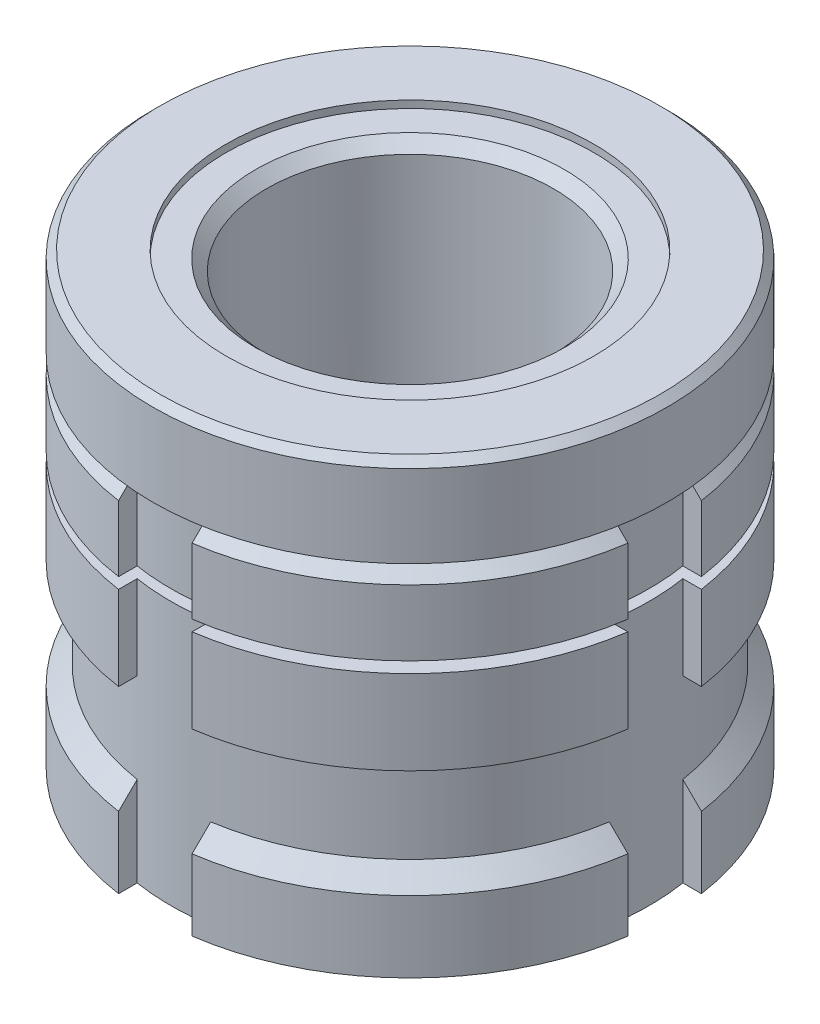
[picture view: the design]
ISO-10303-21;
HEADER;
FILE_DESCRIPTION(('STEP AP214'),'2;1');
FILE_NAME('part.step','',(''),(''),'','','');
FILE_SCHEMA(('AUTOMOTIVE_DESIGN { 1 0 10303 214 1 1 1 1 }'));
ENDSEC;
DATA;
#1=APPLICATION_CONTEXT('core data for automotive mechanical design processes');
#2=APPLICATION_PROTOCOL_DEFINITION('international standard','automotive_design',2000,#1);
#3=PRODUCT_CONTEXT('',#1,'mechanical');
#4=PRODUCT('Part','Part','',(#3));
#5=PRODUCT_RELATED_PRODUCT_CATEGORY('part','',(#4));
#6=PRODUCT_DEFINITION_FORMATION('','',#4);
#7=PRODUCT_DEFINITION_CONTEXT('part definition',#1,'design');
#8=PRODUCT_DEFINITION('design','',#6,#7);
#9=PRODUCT_DEFINITION_SHAPE('','',#8);
#10=(LENGTH_UNIT() NAMED_UNIT(*) SI_UNIT(.MILLI.,.METRE.));
#11=(NAMED_UNIT(*) PLANE_ANGLE_UNIT() SI_UNIT($,.RADIAN.));
#12=(NAMED_UNIT(*) SI_UNIT($,.STERADIAN.) SOLID_ANGLE_UNIT());
#13=UNCERTAINTY_MEASURE_WITH_UNIT(LENGTH_MEASURE(1.E-05),#10,'distance_accuracy_value','');
#14=(GEOMETRIC_REPRESENTATION_CONTEXT(3) GLOBAL_UNCERTAINTY_ASSIGNED_CONTEXT((#13)) GLOBAL_UNIT_ASSIGNED_CONTEXT((#10,
#11,#12)) REPRESENTATION_CONTEXT('',''));
#15=CARTESIAN_POINT('',(0.,0.,0.));
#16=DIRECTION('',(0.,0.,1.));
#17=DIRECTION('',(1.,0.,0.));
#18=AXIS2_PLACEMENT_3D('',#15,#16,#17);
#19=CARTESIAN_POINT('',(0.,24.4,0.));
#20=DIRECTION('',(0.,-1.,0.));
#21=DIRECTION('',(0.,0.,-1.));
#22=AXIS2_PLACEMENT_3D('',#19,#20,#21);
#23=CYLINDRICAL_SURFACE('',#22,35.);
#24=DIRECTION('',(0.,1.,0.));
#25=VECTOR('',#24,1.);
#26=CARTESIAN_POINT('',(-5.00000000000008,-34.8083763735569,34.6410161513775));
#27=LINE('',#26,#25);
#28=CARTESIAN_POINT('',(-5.00000000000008,12.95,34.6410161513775));
#29=VERTEX_POINT('',#28);
#30=CARTESIAN_POINT('',(-5.00000000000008,21.9,34.6410161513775));
#31=VERTEX_POINT('',#30);
#32=EDGE_CURVE('E630',#29,#31,#27,.T.);
#33=ORIENTED_EDGE('',*,*,#32,.T.);
#34=CARTESIAN_POINT('',(0.,21.9,0.));
#35=DIRECTION('',(0.,1.,0.));
#36=DIRECTION('',(0.,0.,1.));
#37=AXIS2_PLACEMENT_3D('',#34,#35,#36);
#38=CIRCLE('',#37,35.);
#39=CARTESIAN_POINT('',(-34.6410161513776,21.9,4.9999999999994));
#40=VERTEX_POINT('',#39);
#41=EDGE_CURVE('E55',#31,#40,#38,.F.);
#42=ORIENTED_EDGE('',*,*,#41,.T.);
#43=DIRECTION('',(0.,1.,0.));
#44=VECTOR('',#43,1.);
#45=CARTESIAN_POINT('',(-34.6410161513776,-34.8083763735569,4.9999999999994));
#46=LINE('',#45,#44);
#47=CARTESIAN_POINT('',(-34.6410161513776,12.95,4.9999999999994));
#48=VERTEX_POINT('',#47);
#49=EDGE_CURVE('E723',#48,#40,#46,.T.);
#50=ORIENTED_EDGE('',*,*,#49,.F.);
#51=CARTESIAN_POINT('',(0.,12.95,0.));
#52=DIRECTION('',(0.,1.,0.));
#53=DIRECTION('',(0.,0.,1.));
#54=AXIS2_PLACEMENT_3D('',#51,#52,#53);
#55=CIRCLE('',#54,35.);
#56=EDGE_CURVE('E632',#48,#29,#55,.T.);
#57=ORIENTED_EDGE('',*,*,#56,.T.);
#58=EDGE_LOOP('',(#33,#42,#50,#57));
#59=FACE_BOUND('',#58,.T.);
#60=ADVANCED_FACE('F39',(#59),#23,.T.);
#61=DIRECTION('',(0.,1.,0.));
#62=VECTOR('',#61,1.);
#63=CARTESIAN_POINT('',(-34.6410161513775,-34.8083763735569,-5.0000000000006));
#64=LINE('',#63,#62);
#65=CARTESIAN_POINT('',(-34.6410161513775,12.95,-5.0000000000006));
#66=VERTEX_POINT('',#65);
#67=CARTESIAN_POINT('',(-34.6410161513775,21.9,-5.0000000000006));
#68=VERTEX_POINT('',#67);
#69=EDGE_CURVE('E714',#66,#68,#64,.T.);
#70=ORIENTED_EDGE('',*,*,#69,.T.);
#71=CARTESIAN_POINT('',(0.,21.9,0.));
#72=DIRECTION('',(0.,1.,0.));
#73=DIRECTION('',(0.,0.,1.));
#74=AXIS2_PLACEMENT_3D('',#71,#72,#73);
#75=CIRCLE('',#74,35.);
#76=CARTESIAN_POINT('',(-5.00000000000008,21.9,-34.6410161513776));
#77=VERTEX_POINT('',#76);
#78=EDGE_CURVE('E409',#68,#77,#75,.F.);
#79=ORIENTED_EDGE('',*,*,#78,.T.);
#80=DIRECTION('',(0.,1.,0.));
#81=VECTOR('',#80,1.);
#82=CARTESIAN_POINT('',(-5.00000000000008,-34.8083763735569,-34.6410161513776));
#83=LINE('',#82,#81);
#84=CARTESIAN_POINT('',(-5.00000000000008,12.95,-34.6410161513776));
#85=VERTEX_POINT('',#84);
#86=EDGE_CURVE('E750',#85,#77,#83,.T.);
#87=ORIENTED_EDGE('',*,*,#86,.F.);
#88=EDGE_CURVE('E1121',#85,#66,#55,.T.);
#89=ORIENTED_EDGE('',*,*,#88,.T.);
#90=EDGE_LOOP('',(#70,#79,#87,#89));
#91=FACE_BOUND('',#90,.T.);
#92=ADVANCED_FACE('F624',(#91),#23,.T.);
#93=DIRECTION('',(0.,1.,0.));
#94=VECTOR('',#93,1.);
#95=CARTESIAN_POINT('',(34.6410161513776,-34.8083763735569,5.00000000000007));
#96=LINE('',#95,#94);
#97=CARTESIAN_POINT('',(34.6410161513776,12.95,5.00000000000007));
#98=VERTEX_POINT('',#97);
#99=CARTESIAN_POINT('',(34.6410161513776,21.9,5.00000000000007));
#100=VERTEX_POINT('',#99);
#101=EDGE_CURVE('E769',#98,#100,#96,.T.);
#102=ORIENTED_EDGE('',*,*,#101,.T.);
#103=CARTESIAN_POINT('',(0.,21.9,0.));
#104=DIRECTION('',(0.,1.,0.));
#105=DIRECTION('',(0.,0.,1.));
#106=AXIS2_PLACEMENT_3D('',#103,#104,#105);
#107=CIRCLE('',#106,35.);
#108=CARTESIAN_POINT('',(5.00000000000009,21.9,34.6410161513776));
#109=VERTEX_POINT('',#108);
#110=EDGE_CURVE('E1137',#100,#109,#107,.F.);
#111=ORIENTED_EDGE('',*,*,#110,.T.);
#112=DIRECTION('',(0.,1.,0.));
#113=VECTOR('',#112,1.);
#114=CARTESIAN_POINT('',(5.00000000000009,-34.8083763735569,34.6410161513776));
#115=LINE('',#114,#113);
#116=CARTESIAN_POINT('',(5.00000000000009,12.95,34.6410161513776));
#117=VERTEX_POINT('',#116);
#118=EDGE_CURVE('E824',#117,#109,#115,.T.);
#119=ORIENTED_EDGE('',*,*,#118,.F.);
#120=EDGE_CURVE('E976',#117,#98,#55,.T.);
#121=ORIENTED_EDGE('',*,*,#120,.T.);
#122=EDGE_LOOP('',(#102,#111,#119,#121));
#123=FACE_BOUND('',#122,.T.);
#124=ADVANCED_FACE('F603',(#123),#23,.T.);
#125=CARTESIAN_POINT('',(0.,12.95,35.));
#126=DIRECTION('',(0.,1.,0.));
#127=DIRECTION('',(0.,0.,1.));
#128=AXIS2_PLACEMENT_3D('',#125,#126,#127);
#129=PLANE('',#128);
#130=CARTESIAN_POINT('',(0.,12.95,0.));
#131=DIRECTION('',(0.,1.,0.));
#132=DIRECTION('',(0.,0.,1.));
#133=AXIS2_PLACEMENT_3D('',#130,#131,#132);
#134=CIRCLE('',#133,25.);
#135=CARTESIAN_POINT('',(0.,12.95,25.));
#136=VERTEX_POINT('',#135);
#137=EDGE_CURVE('E979',#136,#136,#134,.T.);
#138=ORIENTED_EDGE('',*,*,#137,.T.);
#139=EDGE_LOOP('',(#138));
#140=FACE_BOUND('',#139,.T.);
#141=ORIENTED_EDGE('',*,*,#56,.F.);
#142=DIRECTION('',(1.,0.,0.));
#143=VECTOR('',#142,1.);
#144=CARTESIAN_POINT('',(0.,12.95,4.9999999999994));
#145=LINE('',#144,#143);
#146=CARTESIAN_POINT('',(-32.1130814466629,12.95,4.9999999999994));
#147=VERTEX_POINT('',#146);
#148=EDGE_CURVE('E949',#48,#147,#145,.T.);
#149=ORIENTED_EDGE('',*,*,#148,.T.);
#150=CARTESIAN_POINT('',(0.,12.95,0.));
#151=DIRECTION('',(0.,1.,0.));
#152=DIRECTION('',(0.,0.,1.));
#153=AXIS2_PLACEMENT_3D('',#150,#151,#152);
#154=CIRCLE('',#153,32.5);
#155=CARTESIAN_POINT('',(-32.1130814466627,12.95,-5.0000000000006));
#156=VERTEX_POINT('',#155);
#157=EDGE_CURVE('E938',#147,#156,#154,.F.);
#158=ORIENTED_EDGE('',*,*,#157,.T.);
#159=DIRECTION('',(-1.,0.,0.));
#160=VECTOR('',#159,1.);
#161=CARTESIAN_POINT('',(0.,12.95,-5.0000000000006));
#162=LINE('',#161,#160);
#163=EDGE_CURVE('E930',#156,#66,#162,.T.);
#164=ORIENTED_EDGE('',*,*,#163,.T.);
#165=ORIENTED_EDGE('',*,*,#88,.F.);
#166=DIRECTION('',(0.,0.,1.));
#167=VECTOR('',#166,1.);
#168=CARTESIAN_POINT('',(-5.00000000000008,12.95,35.));
#169=LINE('',#168,#167);
#170=CARTESIAN_POINT('',(-5.00000000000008,12.95,-32.1130814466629));
#171=VERTEX_POINT('',#170);
#172=EDGE_CURVE('E918',#85,#171,#169,.T.);
#173=ORIENTED_EDGE('',*,*,#172,.T.);
#174=CARTESIAN_POINT('',(0.,12.95,0.));
#175=DIRECTION('',(0.,1.,0.));
#176=DIRECTION('',(0.,0.,1.));
#177=AXIS2_PLACEMENT_3D('',#174,#175,#176);
#178=CIRCLE('',#177,32.5000000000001);
#179=CARTESIAN_POINT('',(5.00000000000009,12.95,-32.1130814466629));
#180=VERTEX_POINT('',#179);
#181=EDGE_CURVE('E907',#171,#180,#178,.F.);
#182=ORIENTED_EDGE('',*,*,#181,.T.);
#183=DIRECTION('',(0.,0.,-1.));
#184=VECTOR('',#183,1.);
#185=CARTESIAN_POINT('',(5.00000000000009,12.95,35.));
#186=LINE('',#185,#184);
#187=CARTESIAN_POINT('',(5.00000000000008,12.95,-34.6410161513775));
#188=VERTEX_POINT('',#187);
#189=EDGE_CURVE('E368',#180,#188,#186,.T.);
#190=ORIENTED_EDGE('',*,*,#189,.T.);
#191=CARTESIAN_POINT('',(34.6410161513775,12.95,-5.0000000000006));
#192=VERTEX_POINT('',#191);
#193=EDGE_CURVE('E980',#192,#188,#55,.T.);
#194=ORIENTED_EDGE('',*,*,#193,.F.);
#195=DIRECTION('',(-1.,0.,0.));
#196=VECTOR('',#195,1.);
#197=CARTESIAN_POINT('',(0.,12.95,-5.0000000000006));
#198=LINE('',#197,#196);
#199=CARTESIAN_POINT('',(32.1130814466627,12.95,-5.0000000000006));
#200=VERTEX_POINT('',#199);
#201=EDGE_CURVE('E877',#192,#200,#198,.T.);
#202=ORIENTED_EDGE('',*,*,#201,.T.);
#203=CARTESIAN_POINT('',(0.,12.95,0.));
#204=DIRECTION('',(0.,1.,0.));
#205=DIRECTION('',(0.,0.,1.));
#206=AXIS2_PLACEMENT_3D('',#203,#204,#205);
#207=CIRCLE('',#206,32.5);
#208=CARTESIAN_POINT('',(32.1130814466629,12.95,5.00000000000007));
#209=VERTEX_POINT('',#208);
#210=EDGE_CURVE('E865',#200,#209,#207,.F.);
#211=ORIENTED_EDGE('',*,*,#210,.T.);
#212=DIRECTION('',(1.,0.,0.));
#213=VECTOR('',#212,1.);
#214=CARTESIAN_POINT('',(0.,12.95,5.00000000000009));
#215=LINE('',#214,#213);
#216=EDGE_CURVE('E889',#209,#98,#215,.T.);
#217=ORIENTED_EDGE('',*,*,#216,.T.);
#218=ORIENTED_EDGE('',*,*,#120,.F.);
#219=DIRECTION('',(0.,0.,-1.));
#220=VECTOR('',#219,1.);
#221=CARTESIAN_POINT('',(5.00000000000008,12.95,35.));
#222=LINE('',#221,#220);
#223=CARTESIAN_POINT('',(5.00000000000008,12.95,32.1130814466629));
#224=VERTEX_POINT('',#223);
#225=EDGE_CURVE('E846',#117,#224,#222,.T.);
#226=ORIENTED_EDGE('',*,*,#225,.T.);
#227=CARTESIAN_POINT('',(0.,12.95,0.));
#228=DIRECTION('',(0.,1.,0.));
#229=DIRECTION('',(0.,0.,1.));
#230=AXIS2_PLACEMENT_3D('',#227,#228,#229);
#231=CIRCLE('',#230,32.5);
#232=CARTESIAN_POINT('',(-5.00000000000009,12.95,32.1130814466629));
#233=VERTEX_POINT('',#232);
#234=EDGE_CURVE('E834',#224,#233,#231,.F.);
#235=ORIENTED_EDGE('',*,*,#234,.T.);
#236=DIRECTION('',(0.,0.,1.));
#237=VECTOR('',#236,1.);
#238=CARTESIAN_POINT('',(-5.00000000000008,12.95,35.));
#239=LINE('',#238,#237);
#240=EDGE_CURVE('E858',#233,#29,#239,.T.);
#241=ORIENTED_EDGE('',*,*,#240,.T.);
#242=EDGE_LOOP('',(#141,#149,#158,#164,#165,#173,#182,#190,#194,#202,#211,#217,#218,#226,#235,#241));
#243=FACE_BOUND('',#242,.T.);
#244=ADVANCED_FACE('F599',(#140,#243),#129,.F.);
#245=CARTESIAN_POINT('',(0.,11.45,35.));
#246=DIRECTION('',(0.,-1.,0.));
#247=DIRECTION('',(0.,0.,-1.));
#248=AXIS2_PLACEMENT_3D('',#245,#246,#247);
#249=PLANE('',#248);
#250=CARTESIAN_POINT('',(0.,11.45,0.));
#251=DIRECTION('',(0.,1.,0.));
#252=DIRECTION('',(0.,0.,1.));
#253=AXIS2_PLACEMENT_3D('',#250,#251,#252);
#254=CIRCLE('',#253,25.);
#255=CARTESIAN_POINT('',(0.,11.45,25.));
#256=VERTEX_POINT('',#255);
#257=EDGE_CURVE('E958',#256,#256,#254,.T.);
#258=ORIENTED_EDGE('',*,*,#257,.F.);
#259=EDGE_LOOP('',(#258));
#260=FACE_BOUND('',#259,.T.);
#261=CARTESIAN_POINT('',(0.,11.45,0.));
#262=DIRECTION('',(0.,-1.,0.));
#263=DIRECTION('',(0.,0.,-1.));
#264=AXIS2_PLACEMENT_3D('',#261,#262,#263);
#265=CIRCLE('',#264,32.5);
#266=CARTESIAN_POINT('',(-32.1130814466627,11.45,-5.0000000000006));
#267=VERTEX_POINT('',#266);
#268=CARTESIAN_POINT('',(-32.1130814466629,11.45,4.9999999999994));
#269=VERTEX_POINT('',#268);
#270=EDGE_CURVE('E934',#267,#269,#265,.F.);
#271=ORIENTED_EDGE('',*,*,#270,.T.);
#272=DIRECTION('',(-1.,0.,0.));
#273=VECTOR('',#272,1.);
#274=CARTESIAN_POINT('',(0.,11.45,4.9999999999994));
#275=LINE('',#274,#273);
#276=CARTESIAN_POINT('',(-34.6410161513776,11.45,4.9999999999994));
#277=VERTEX_POINT('',#276);
#278=EDGE_CURVE('E945',#269,#277,#275,.T.);
#279=ORIENTED_EDGE('',*,*,#278,.T.);
#280=CARTESIAN_POINT('',(0.,11.45,0.));
#281=DIRECTION('',(0.,1.,0.));
#282=DIRECTION('',(0.,0.,1.));
#283=AXIS2_PLACEMENT_3D('',#280,#281,#282);
#284=CIRCLE('',#283,35.);
#285=CARTESIAN_POINT('',(-5.00000000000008,11.45,34.6410161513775));
#286=VERTEX_POINT('',#285);
#287=EDGE_CURVE('E970',#277,#286,#284,.T.);
#288=ORIENTED_EDGE('',*,*,#287,.T.);
#289=DIRECTION('',(0.,0.,-1.));
#290=VECTOR('',#289,1.);
#291=CARTESIAN_POINT('',(-5.00000000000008,11.45,35.));
#292=LINE('',#291,#290);
#293=CARTESIAN_POINT('',(-5.00000000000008,11.45,32.1130814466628));
#294=VERTEX_POINT('',#293);
#295=EDGE_CURVE('E854',#286,#294,#292,.T.);
#296=ORIENTED_EDGE('',*,*,#295,.T.);
#297=CARTESIAN_POINT('',(0.,11.45,0.));
#298=DIRECTION('',(0.,-1.,0.));
#299=DIRECTION('',(0.,0.,-1.));
#300=AXIS2_PLACEMENT_3D('',#297,#298,#299);
#301=CIRCLE('',#300,32.5);
#302=CARTESIAN_POINT('',(5.00000000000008,11.45,32.1130814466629));
#303=VERTEX_POINT('',#302);
#304=EDGE_CURVE('E732',#294,#303,#301,.F.);
#305=ORIENTED_EDGE('',*,*,#304,.T.);
#306=DIRECTION('',(0.,0.,1.));
#307=VECTOR('',#306,1.);
#308=CARTESIAN_POINT('',(5.00000000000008,11.45,35.));
#309=LINE('',#308,#307);
#310=CARTESIAN_POINT('',(5.00000000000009,11.45,34.6410161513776));
#311=VERTEX_POINT('',#310);
#312=EDGE_CURVE('E842',#303,#311,#309,.T.);
#313=ORIENTED_EDGE('',*,*,#312,.T.);
#314=CARTESIAN_POINT('',(34.6410161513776,11.45,5.00000000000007));
#315=VERTEX_POINT('',#314);
#316=EDGE_CURVE('E971',#311,#315,#284,.T.);
#317=ORIENTED_EDGE('',*,*,#316,.T.);
#318=DIRECTION('',(-1.,0.,0.));
#319=VECTOR('',#318,1.);
#320=CARTESIAN_POINT('',(0.,11.45,5.00000000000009));
#321=LINE('',#320,#319);
#322=CARTESIAN_POINT('',(32.1130814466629,11.45,5.00000000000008));
#323=VERTEX_POINT('',#322);
#324=EDGE_CURVE('E885',#315,#323,#321,.T.);
#325=ORIENTED_EDGE('',*,*,#324,.T.);
#326=CARTESIAN_POINT('',(0.,11.45,0.));
#327=DIRECTION('',(0.,-1.,0.));
#328=DIRECTION('',(0.,0.,-1.));
#329=AXIS2_PLACEMENT_3D('',#326,#327,#328);
#330=CIRCLE('',#329,32.5);
#331=CARTESIAN_POINT('',(32.1130814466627,11.45,-5.0000000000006));
#332=VERTEX_POINT('',#331);
#333=EDGE_CURVE('E861',#323,#332,#330,.F.);
#334=ORIENTED_EDGE('',*,*,#333,.T.);
#335=DIRECTION('',(1.,0.,0.));
#336=VECTOR('',#335,1.);
#337=CARTESIAN_POINT('',(0.,11.45,-5.0000000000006));
#338=LINE('',#337,#336);
#339=CARTESIAN_POINT('',(34.6410161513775,11.45,-5.0000000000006));
#340=VERTEX_POINT('',#339);
#341=EDGE_CURVE('E873',#332,#340,#338,.T.);
#342=ORIENTED_EDGE('',*,*,#341,.T.);
#343=CARTESIAN_POINT('',(5.00000000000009,11.45,-34.6410161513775));
#344=VERTEX_POINT('',#343);
#345=EDGE_CURVE('E975',#340,#344,#284,.T.);
#346=ORIENTED_EDGE('',*,*,#345,.T.);
#347=DIRECTION('',(0.,0.,1.));
#348=VECTOR('',#347,1.);
#349=CARTESIAN_POINT('',(5.00000000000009,11.45,35.));
#350=LINE('',#349,#348);
#351=CARTESIAN_POINT('',(5.00000000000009,11.45,-32.1130814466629));
#352=VERTEX_POINT('',#351);
#353=EDGE_CURVE('E897',#344,#352,#350,.T.);
#354=ORIENTED_EDGE('',*,*,#353,.T.);
#355=CARTESIAN_POINT('',(0.,11.45,0.));
#356=DIRECTION('',(0.,-1.,0.));
#357=DIRECTION('',(0.,0.,-1.));
#358=AXIS2_PLACEMENT_3D('',#355,#356,#357);
#359=CIRCLE('',#358,32.5000000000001);
#360=CARTESIAN_POINT('',(-5.00000000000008,11.45,-32.1130814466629));
#361=VERTEX_POINT('',#360);
#362=EDGE_CURVE('E903',#352,#361,#359,.F.);
#363=ORIENTED_EDGE('',*,*,#362,.T.);
#364=DIRECTION('',(0.,0.,-1.));
#365=VECTOR('',#364,1.);
#366=CARTESIAN_POINT('',(-5.00000000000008,11.45,35.));
#367=LINE('',#366,#365);
#368=CARTESIAN_POINT('',(-5.00000000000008,11.45,-34.6410161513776));
#369=VERTEX_POINT('',#368);
#370=EDGE_CURVE('E914',#361,#369,#367,.T.);
#371=ORIENTED_EDGE('',*,*,#370,.T.);
#372=CARTESIAN_POINT('',(-34.6410161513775,11.45,-5.0000000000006));
#373=VERTEX_POINT('',#372);
#374=EDGE_CURVE('E1180',#369,#373,#284,.T.);
#375=ORIENTED_EDGE('',*,*,#374,.T.);
#376=DIRECTION('',(1.,0.,0.));
#377=VECTOR('',#376,1.);
#378=CARTESIAN_POINT('',(0.,11.45,-5.0000000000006));
#379=LINE('',#378,#377);
#380=EDGE_CURVE('E926',#373,#267,#379,.T.);
#381=ORIENTED_EDGE('',*,*,#380,.T.);
#382=EDGE_LOOP('',(#271,#279,#288,#296,#305,#313,#317,#325,#334,#342,#346,#354,#363,#371,#375,#381));
#383=FACE_BOUND('',#382,.T.);
#384=ADVANCED_FACE('F595',(#260,#383),#249,.F.);
#385=CARTESIAN_POINT('',(0.,0.,0.));
#386=DIRECTION('',(0.,1.,0.));
#387=DIRECTION('',(0.,0.,1.));
#388=AXIS2_PLACEMENT_3D('',#385,#386,#387);
#389=PLANE('',#388);
#390=CARTESIAN_POINT('',(0.,0.,0.));
#391=DIRECTION('',(0.,1.,0.));
#392=DIRECTION('',(0.,0.,1.));
#393=AXIS2_PLACEMENT_3D('',#390,#391,#392);
#394=CIRCLE('',#393,35.);
#395=CARTESIAN_POINT('',(-34.6410161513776,0.,4.9999999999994));
#396=VERTEX_POINT('',#395);
#397=CARTESIAN_POINT('',(-5.00000000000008,0.,34.6410161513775));
#398=VERTEX_POINT('',#397);
#399=EDGE_CURVE('E984',#396,#398,#394,.T.);
#400=ORIENTED_EDGE('',*,*,#399,.F.);
#401=DIRECTION('',(1.,0.,0.));
#402=VECTOR('',#401,1.);
#403=CARTESIAN_POINT('',(0.,0.,4.9999999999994));
#404=LINE('',#403,#402);
#405=CARTESIAN_POINT('',(-32.1130814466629,0.,4.9999999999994));
#406=VERTEX_POINT('',#405);
#407=EDGE_CURVE('E941',#396,#406,#404,.T.);
#408=ORIENTED_EDGE('',*,*,#407,.T.);
#409=CARTESIAN_POINT('',(0.,0.,0.));
#410=DIRECTION('',(0.,-1.,0.));
#411=DIRECTION('',(0.,0.,-1.));
#412=AXIS2_PLACEMENT_3D('',#409,#410,#411);
#413=CIRCLE('',#412,32.5);
#414=CARTESIAN_POINT('',(-5.00000000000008,0.,32.1130814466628));
#415=VERTEX_POINT('',#414);
#416=EDGE_CURVE('E1077',#415,#406,#413,.T.);
#417=ORIENTED_EDGE('',*,*,#416,.F.);
#418=DIRECTION('',(0.,0.,1.));
#419=VECTOR('',#418,1.);
#420=CARTESIAN_POINT('',(-5.00000000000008,0.,0.));
#421=LINE('',#420,#419);
#422=EDGE_CURVE('E850',#415,#398,#421,.T.);
#423=ORIENTED_EDGE('',*,*,#422,.T.);
#424=EDGE_LOOP('',(#400,#408,#417,#423));
#425=FACE_BOUND('',#424,.T.);
#426=ADVANCED_FACE('F598',(#425),#389,.F.);
#427=CARTESIAN_POINT('',(-32.1130814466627,0.,-5.0000000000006));
#428=VERTEX_POINT('',#427);
#429=CARTESIAN_POINT('',(-5.00000000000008,0.,-32.1130814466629));
#430=VERTEX_POINT('',#429);
#431=EDGE_CURVE('E966',#428,#430,#413,.T.);
#432=ORIENTED_EDGE('',*,*,#431,.F.);
#433=DIRECTION('',(-1.,0.,0.));
#434=VECTOR('',#433,1.);
#435=CARTESIAN_POINT('',(0.,0.,-5.0000000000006));
#436=LINE('',#435,#434);
#437=CARTESIAN_POINT('',(-34.6410161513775,0.,-5.0000000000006));
#438=VERTEX_POINT('',#437);
#439=EDGE_CURVE('E922',#428,#438,#436,.T.);
#440=ORIENTED_EDGE('',*,*,#439,.T.);
#441=CARTESIAN_POINT('',(-5.00000000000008,0.,-34.6410161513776));
#442=VERTEX_POINT('',#441);
#443=EDGE_CURVE('E1080',#442,#438,#394,.T.);
#444=ORIENTED_EDGE('',*,*,#443,.F.);
#445=DIRECTION('',(0.,0.,1.));
#446=VECTOR('',#445,1.);
#447=CARTESIAN_POINT('',(-5.00000000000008,0.,0.));
#448=LINE('',#447,#446);
#449=EDGE_CURVE('E910',#442,#430,#448,.T.);
#450=ORIENTED_EDGE('',*,*,#449,.T.);
#451=EDGE_LOOP('',(#432,#440,#444,#450));
#452=FACE_BOUND('',#451,.T.);
#453=ADVANCED_FACE('F618',(#452),#389,.F.);
#454=CARTESIAN_POINT('',(32.1130814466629,0.,5.00000000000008));
#455=VERTEX_POINT('',#454);
#456=CARTESIAN_POINT('',(5.00000000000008,0.,32.1130814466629));
#457=VERTEX_POINT('',#456);
#458=EDGE_CURVE('E965',#455,#457,#413,.T.);
#459=ORIENTED_EDGE('',*,*,#458,.F.);
#460=DIRECTION('',(1.,0.,0.));
#461=VECTOR('',#460,1.);
#462=CARTESIAN_POINT('',(0.,0.,5.00000000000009));
#463=LINE('',#462,#461);
#464=CARTESIAN_POINT('',(34.6410161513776,0.,5.00000000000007));
#465=VERTEX_POINT('',#464);
#466=EDGE_CURVE('E881',#455,#465,#463,.T.);
#467=ORIENTED_EDGE('',*,*,#466,.T.);
#468=CARTESIAN_POINT('',(5.00000000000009,0.,34.6410161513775));
#469=VERTEX_POINT('',#468);
#470=EDGE_CURVE('E985',#469,#465,#394,.T.);
#471=ORIENTED_EDGE('',*,*,#470,.F.);
#472=DIRECTION('',(0.,0.,-1.));
#473=VECTOR('',#472,1.);
#474=CARTESIAN_POINT('',(5.00000000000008,0.,0.));
#475=LINE('',#474,#473);
#476=EDGE_CURVE('E838',#469,#457,#475,.T.);
#477=ORIENTED_EDGE('',*,*,#476,.T.);
#478=EDGE_LOOP('',(#459,#467,#471,#477));
#479=FACE_BOUND('',#478,.T.);
#480=ADVANCED_FACE('F611',(#479),#389,.F.);
#481=ORIENTED_EDGE('',*,*,#287,.F.);
#482=EDGE_CURVE('E733',#396,#277,#46,.T.);
#483=ORIENTED_EDGE('',*,*,#482,.F.);
#484=ORIENTED_EDGE('',*,*,#399,.T.);
#485=EDGE_CURVE('E636',#398,#286,#27,.T.);
#486=ORIENTED_EDGE('',*,*,#485,.T.);
#487=EDGE_LOOP('',(#481,#483,#484,#486));
#488=FACE_BOUND('',#487,.T.);
#489=ADVANCED_FACE('F621',(#488),#23,.T.);
#490=ORIENTED_EDGE('',*,*,#443,.T.);
#491=EDGE_CURVE('E724',#438,#373,#64,.T.);
#492=ORIENTED_EDGE('',*,*,#491,.T.);
#493=ORIENTED_EDGE('',*,*,#374,.F.);
#494=EDGE_CURVE('E761',#442,#369,#83,.T.);
#495=ORIENTED_EDGE('',*,*,#494,.F.);
#496=EDGE_LOOP('',(#490,#492,#493,#495));
#497=FACE_BOUND('',#496,.T.);
#498=ADVANCED_FACE('F1181',(#497),#23,.T.);
#499=ORIENTED_EDGE('',*,*,#470,.T.);
#500=EDGE_CURVE('E795',#465,#315,#96,.T.);
#501=ORIENTED_EDGE('',*,*,#500,.T.);
#502=ORIENTED_EDGE('',*,*,#316,.F.);
#503=EDGE_CURVE('E823',#469,#311,#115,.T.);
#504=ORIENTED_EDGE('',*,*,#503,.F.);
#505=EDGE_LOOP('',(#499,#501,#502,#504));
#506=FACE_BOUND('',#505,.T.);
#507=ADVANCED_FACE('F1204',(#506),#23,.T.);
#508=CARTESIAN_POINT('',(0.,-12.2,0.));
#509=DIRECTION('',(0.,-1.,0.));
#510=DIRECTION('',(0.,0.,-1.));
#511=AXIS2_PLACEMENT_3D('',#508,#509,#510);
#512=CYLINDRICAL_SURFACE('',#511,35.);
#513=CARTESIAN_POINT('',(-5.00000000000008,-24.4,34.6410161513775));
#514=VERTEX_POINT('',#513);
#515=CARTESIAN_POINT('',(-5.00000000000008,-14.7,34.6410161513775));
#516=VERTEX_POINT('',#515);
#517=EDGE_CURVE('E639',#514,#516,#27,.T.);
#518=ORIENTED_EDGE('',*,*,#517,.T.);
#519=CARTESIAN_POINT('',(0.,-14.7,0.));
#520=DIRECTION('',(0.,-1.,0.));
#521=DIRECTION('',(0.,0.,-1.));
#522=AXIS2_PLACEMENT_3D('',#519,#520,#521);
#523=CIRCLE('',#522,35.);
#524=CARTESIAN_POINT('',(-34.6410161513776,-14.7,4.9999999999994));
#525=VERTEX_POINT('',#524);
#526=EDGE_CURVE('E532',#516,#525,#523,.T.);
#527=ORIENTED_EDGE('',*,*,#526,.T.);
#528=CARTESIAN_POINT('',(-34.6410161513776,-24.4,4.9999999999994));
#529=VERTEX_POINT('',#528);
#530=EDGE_CURVE('E730',#529,#525,#46,.T.);
#531=ORIENTED_EDGE('',*,*,#530,.F.);
#532=CARTESIAN_POINT('',(0.,-24.4,0.));
#533=DIRECTION('',(0.,-1.,0.));
#534=DIRECTION('',(0.,0.,-1.));
#535=AXIS2_PLACEMENT_3D('',#532,#533,#534);
#536=CIRCLE('',#535,35.);
#537=EDGE_CURVE('E689',#514,#529,#536,.T.);
#538=ORIENTED_EDGE('',*,*,#537,.F.);
#539=EDGE_LOOP('',(#518,#527,#531,#538));
#540=FACE_BOUND('',#539,.T.);
#541=ADVANCED_FACE('F584',(#540),#512,.T.);
#542=CARTESIAN_POINT('',(-34.6410161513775,-24.4,-5.0000000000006));
#543=VERTEX_POINT('',#542);
#544=CARTESIAN_POINT('',(-34.6410161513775,-14.7,-5.0000000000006));
#545=VERTEX_POINT('',#544);
#546=EDGE_CURVE('E719',#543,#545,#64,.T.);
#547=ORIENTED_EDGE('',*,*,#546,.T.);
#548=CARTESIAN_POINT('',(0.,-14.7,0.));
#549=DIRECTION('',(0.,-1.,0.));
#550=DIRECTION('',(0.,0.,-1.));
#551=AXIS2_PLACEMENT_3D('',#548,#549,#550);
#552=CIRCLE('',#551,35.);
#553=CARTESIAN_POINT('',(-5.00000000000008,-14.7,-34.6410161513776));
#554=VERTEX_POINT('',#553);
#555=EDGE_CURVE('E992',#545,#554,#552,.T.);
#556=ORIENTED_EDGE('',*,*,#555,.T.);
#557=CARTESIAN_POINT('',(-5.00000000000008,-24.4,-34.6410161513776));
#558=VERTEX_POINT('',#557);
#559=EDGE_CURVE('E707',#558,#554,#83,.T.);
#560=ORIENTED_EDGE('',*,*,#559,.F.);
#561=EDGE_CURVE('E953',#543,#558,#536,.T.);
#562=ORIENTED_EDGE('',*,*,#561,.F.);
#563=EDGE_LOOP('',(#547,#556,#560,#562));
#564=FACE_BOUND('',#563,.T.);
#565=ADVANCED_FACE('F1040',(#564),#512,.T.);
#566=CARTESIAN_POINT('',(34.6410161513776,-24.4,5.00000000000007));
#567=VERTEX_POINT('',#566);
#568=CARTESIAN_POINT('',(34.6410161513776,-14.7,5.00000000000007));
#569=VERTEX_POINT('',#568);
#570=EDGE_CURVE('E791',#567,#569,#96,.T.);
#571=ORIENTED_EDGE('',*,*,#570,.T.);
#572=CARTESIAN_POINT('',(0.,-14.7,0.));
#573=DIRECTION('',(0.,-1.,0.));
#574=DIRECTION('',(0.,0.,-1.));
#575=AXIS2_PLACEMENT_3D('',#572,#573,#574);
#576=CIRCLE('',#575,35.);
#577=CARTESIAN_POINT('',(5.00000000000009,-14.7,34.6410161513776));
#578=VERTEX_POINT('',#577);
#579=EDGE_CURVE('E1148',#569,#578,#576,.T.);
#580=ORIENTED_EDGE('',*,*,#579,.T.);
#581=CARTESIAN_POINT('',(5.00000000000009,-24.4,34.6410161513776));
#582=VERTEX_POINT('',#581);
#583=EDGE_CURVE('E816',#582,#578,#115,.T.);
#584=ORIENTED_EDGE('',*,*,#583,.F.);
#585=EDGE_CURVE('E959',#567,#582,#536,.T.);
#586=ORIENTED_EDGE('',*,*,#585,.F.);
#587=EDGE_LOOP('',(#571,#580,#584,#586));
#588=FACE_BOUND('',#587,.T.);
#589=ADVANCED_FACE('F585',(#588),#512,.T.);
#590=CARTESIAN_POINT('',(0.,-24.4,0.));
#591=DIRECTION('',(0.,-1.,0.));
#592=DIRECTION('',(0.,0.,-1.));
#593=AXIS2_PLACEMENT_3D('',#590,#591,#592);
#594=PLANE('',#593);
#595=CARTESIAN_POINT('',(0.,-24.4,0.));
#596=DIRECTION('',(0.,-1.,0.));
#597=DIRECTION('',(0.,0.,-1.));
#598=AXIS2_PLACEMENT_3D('',#595,#596,#597);
#599=CIRCLE('',#598,21.);
#600=CARTESIAN_POINT('',(0.,-24.4,-21.));
#601=VERTEX_POINT('',#600);
#602=EDGE_CURVE('E661',#601,#601,#599,.F.);
#603=ORIENTED_EDGE('',*,*,#602,.T.);
#604=EDGE_LOOP('',(#603));
#605=FACE_BOUND('',#604,.T.);
#606=DIRECTION('',(1.,0.,0.));
#607=VECTOR('',#606,1.);
#608=CARTESIAN_POINT('',(-32.1130814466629,-24.4,4.9999999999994));
#609=LINE('',#608,#607);
#610=CARTESIAN_POINT('',(-32.1130814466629,-24.4,4.9999999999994));
#611=VERTEX_POINT('',#610);
#612=EDGE_CURVE('E684',#529,#611,#609,.T.);
#613=ORIENTED_EDGE('',*,*,#612,.T.);
#614=CARTESIAN_POINT('',(0.,-24.4,0.));
#615=DIRECTION('',(0.,-1.,0.));
#616=DIRECTION('',(0.,0.,-1.));
#617=AXIS2_PLACEMENT_3D('',#614,#615,#616);
#618=CIRCLE('',#617,32.5);
#619=CARTESIAN_POINT('',(-32.1130814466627,-24.4,-5.0000000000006));
#620=VERTEX_POINT('',#619);
#621=EDGE_CURVE('E686',#611,#620,#618,.T.);
#622=ORIENTED_EDGE('',*,*,#621,.T.);
#623=DIRECTION('',(-1.,0.,0.));
#624=VECTOR('',#623,1.);
#625=CARTESIAN_POINT('',(-34.6410161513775,-24.4,-5.0000000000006));
#626=LINE('',#625,#624);
#627=EDGE_CURVE('E711',#620,#543,#626,.T.);
#628=ORIENTED_EDGE('',*,*,#627,.T.);
#629=ORIENTED_EDGE('',*,*,#561,.T.);
#630=DIRECTION('',(0.,0.,1.));
#631=VECTOR('',#630,1.);
#632=CARTESIAN_POINT('',(-5.00000000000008,-24.4,-34.6410161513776));
#633=LINE('',#632,#631);
#634=CARTESIAN_POINT('',(-5.00000000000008,-24.4,-32.1130814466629));
#635=VERTEX_POINT('',#634);
#636=EDGE_CURVE('E359',#558,#635,#633,.T.);
#637=ORIENTED_EDGE('',*,*,#636,.T.);
#638=CARTESIAN_POINT('',(0.,-24.4,0.));
#639=DIRECTION('',(0.,-1.,0.));
#640=DIRECTION('',(0.,0.,-1.));
#641=AXIS2_PLACEMENT_3D('',#638,#639,#640);
#642=CIRCLE('',#641,32.5000000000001);
#643=CARTESIAN_POINT('',(5.00000000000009,-24.4,-32.1130814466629));
#644=VERTEX_POINT('',#643);
#645=EDGE_CURVE('E371',#635,#644,#642,.T.);
#646=ORIENTED_EDGE('',*,*,#645,.T.);
#647=DIRECTION('',(0.,0.,-1.));
#648=VECTOR('',#647,1.);
#649=CARTESIAN_POINT('',(5.00000000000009,-24.4,-32.1130814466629));
#650=LINE('',#649,#648);
#651=CARTESIAN_POINT('',(5.00000000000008,-24.4,-34.6410161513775));
#652=VERTEX_POINT('',#651);
#653=EDGE_CURVE('E738',#644,#652,#650,.T.);
#654=ORIENTED_EDGE('',*,*,#653,.T.);
#655=CARTESIAN_POINT('',(34.6410161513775,-24.4,-5.00000000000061));
#656=VERTEX_POINT('',#655);
#657=EDGE_CURVE('E954',#652,#656,#536,.T.);
#658=ORIENTED_EDGE('',*,*,#657,.T.);
#659=DIRECTION('',(-1.,0.,0.));
#660=VECTOR('',#659,1.);
#661=CARTESIAN_POINT('',(32.1130814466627,-24.4,-5.0000000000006));
#662=LINE('',#661,#660);
#663=CARTESIAN_POINT('',(32.1130814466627,-24.4,-5.0000000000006));
#664=VERTEX_POINT('',#663);
#665=EDGE_CURVE('E776',#656,#664,#662,.T.);
#666=ORIENTED_EDGE('',*,*,#665,.T.);
#667=CARTESIAN_POINT('',(0.,-24.4,0.));
#668=DIRECTION('',(0.,-1.,0.));
#669=DIRECTION('',(0.,0.,-1.));
#670=AXIS2_PLACEMENT_3D('',#667,#668,#669);
#671=CIRCLE('',#670,32.5);
#672=CARTESIAN_POINT('',(32.1130814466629,-24.4,5.00000000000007));
#673=VERTEX_POINT('',#672);
#674=EDGE_CURVE('E770',#664,#673,#671,.T.);
#675=ORIENTED_EDGE('',*,*,#674,.T.);
#676=DIRECTION('',(1.,0.,0.));
#677=VECTOR('',#676,1.);
#678=CARTESIAN_POINT('',(34.6410161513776,-24.4,5.00000000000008));
#679=LINE('',#678,#677);
#680=EDGE_CURVE('E764',#673,#567,#679,.T.);
#681=ORIENTED_EDGE('',*,*,#680,.T.);
#682=ORIENTED_EDGE('',*,*,#585,.T.);
#683=DIRECTION('',(0.,0.,-1.));
#684=VECTOR('',#683,1.);
#685=CARTESIAN_POINT('',(5.00000000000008,-24.4,34.6410161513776));
#686=LINE('',#685,#684);
#687=CARTESIAN_POINT('',(5.00000000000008,-24.4,32.1130814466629));
#688=VERTEX_POINT('',#687);
#689=EDGE_CURVE('E812',#582,#688,#686,.T.);
#690=ORIENTED_EDGE('',*,*,#689,.T.);
#691=CARTESIAN_POINT('',(0.,-24.4,0.));
#692=DIRECTION('',(0.,-1.,0.));
#693=DIRECTION('',(0.,0.,-1.));
#694=AXIS2_PLACEMENT_3D('',#691,#692,#693);
#695=CIRCLE('',#694,32.5);
#696=CARTESIAN_POINT('',(-5.00000000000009,-24.4,32.1130814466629));
#697=VERTEX_POINT('',#696);
#698=EDGE_CURVE('E806',#688,#697,#695,.T.);
#699=ORIENTED_EDGE('',*,*,#698,.T.);
#700=DIRECTION('',(0.,0.,1.));
#701=VECTOR('',#700,1.);
#702=CARTESIAN_POINT('',(-5.00000000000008,-24.4,32.1130814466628));
#703=LINE('',#702,#701);
#704=EDGE_CURVE('E637',#697,#514,#703,.T.);
#705=ORIENTED_EDGE('',*,*,#704,.T.);
#706=ORIENTED_EDGE('',*,*,#537,.T.);
#707=EDGE_LOOP('',(#613,#622,#628,#629,#637,#646,#654,#658,#666,#675,#681,#682,#690,#699,#705,#706));
#708=FACE_BOUND('',#707,.T.);
#709=ADVANCED_FACE('F586',(#605,#708),#594,.T.);
#710=CARTESIAN_POINT('',(0.,-24.4,0.));
#711=DIRECTION('',(0.,1.,0.));
#712=DIRECTION('',(0.,0.,1.));
#713=AXIS2_PLACEMENT_3D('',#710,#711,#712);
#714=CYLINDRICAL_SURFACE('',#713,32.5);
#715=DIRECTION('',(0.,1.,0.));
#716=VECTOR('',#715,1.);
#717=CARTESIAN_POINT('',(-32.1130814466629,-34.8083763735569,4.9999999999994));
#718=LINE('',#717,#716);
#719=CARTESIAN_POINT('',(-32.1130814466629,-12.2,4.9999999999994));
#720=VERTEX_POINT('',#719);
#721=EDGE_CURVE('E704',#611,#720,#718,.T.);
#722=ORIENTED_EDGE('',*,*,#721,.T.);
#723=CARTESIAN_POINT('',(0.,-12.2,0.));
#724=DIRECTION('',(0.,-1.,0.));
#725=DIRECTION('',(0.,0.,-1.));
#726=AXIS2_PLACEMENT_3D('',#723,#724,#725);
#727=CIRCLE('',#726,32.5);
#728=CARTESIAN_POINT('',(-5.00000000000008,-12.2,32.1130814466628));
#729=VERTEX_POINT('',#728);
#730=EDGE_CURVE('E1014',#729,#720,#727,.T.);
#731=ORIENTED_EDGE('',*,*,#730,.F.);
#732=DIRECTION('',(0.,1.,0.));
#733=VECTOR('',#732,1.);
#734=CARTESIAN_POINT('',(-5.00000000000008,-34.8083763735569,32.1130814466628));
#735=LINE('',#734,#733);
#736=EDGE_CURVE('E765',#697,#729,#735,.T.);
#737=ORIENTED_EDGE('',*,*,#736,.F.);
#738=ORIENTED_EDGE('',*,*,#698,.F.);
#739=DIRECTION('',(0.,1.,0.));
#740=VECTOR('',#739,1.);
#741=CARTESIAN_POINT('',(5.00000000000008,-34.8083763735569,32.1130814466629));
#742=LINE('',#741,#740);
#743=CARTESIAN_POINT('',(5.00000000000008,-12.2,32.1130814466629));
#744=VERTEX_POINT('',#743);
#745=EDGE_CURVE('E811',#688,#744,#742,.T.);
#746=ORIENTED_EDGE('',*,*,#745,.T.);
#747=CARTESIAN_POINT('',(32.1130814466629,-12.2,5.00000000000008));
#748=VERTEX_POINT('',#747);
#749=EDGE_CURVE('E993',#748,#744,#727,.T.);
#750=ORIENTED_EDGE('',*,*,#749,.F.);
#751=DIRECTION('',(0.,1.,0.));
#752=VECTOR('',#751,1.);
#753=CARTESIAN_POINT('',(32.1130814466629,-34.8083763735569,5.00000000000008));
#754=LINE('',#753,#752);
#755=EDGE_CURVE('E360',#673,#748,#754,.T.);
#756=ORIENTED_EDGE('',*,*,#755,.F.);
#757=ORIENTED_EDGE('',*,*,#674,.F.);
#758=DIRECTION('',(0.,1.,0.));
#759=VECTOR('',#758,1.);
#760=CARTESIAN_POINT('',(32.1130814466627,-34.8083763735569,-5.0000000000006));
#761=LINE('',#760,#759);
#762=CARTESIAN_POINT('',(32.1130814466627,-12.2,-5.0000000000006));
#763=VERTEX_POINT('',#762);
#764=EDGE_CURVE('E775',#664,#763,#761,.T.);
#765=ORIENTED_EDGE('',*,*,#764,.T.);
#766=CARTESIAN_POINT('',(5.00000000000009,-12.2,-32.1130814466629));
#767=VERTEX_POINT('',#766);
#768=EDGE_CURVE('E989',#767,#763,#727,.T.);
#769=ORIENTED_EDGE('',*,*,#768,.F.);
#770=DIRECTION('',(0.,1.,0.));
#771=VECTOR('',#770,1.);
#772=CARTESIAN_POINT('',(5.00000000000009,-34.8083763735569,-32.1130814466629));
#773=LINE('',#772,#771);
#774=EDGE_CURVE('E373',#644,#767,#773,.T.);
#775=ORIENTED_EDGE('',*,*,#774,.F.);
#776=ORIENTED_EDGE('',*,*,#645,.F.);
#777=DIRECTION('',(0.,1.,0.));
#778=VECTOR('',#777,1.);
#779=CARTESIAN_POINT('',(-5.00000000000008,-34.8083763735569,-32.1130814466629));
#780=LINE('',#779,#778);
#781=CARTESIAN_POINT('',(-5.00000000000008,-12.2,-32.1130814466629));
#782=VERTEX_POINT('',#781);
#783=EDGE_CURVE('E746',#635,#782,#780,.T.);
#784=ORIENTED_EDGE('',*,*,#783,.T.);
#785=CARTESIAN_POINT('',(-32.1130814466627,-12.2,-5.0000000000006));
#786=VERTEX_POINT('',#785);
#787=EDGE_CURVE('E964',#786,#782,#727,.T.);
#788=ORIENTED_EDGE('',*,*,#787,.F.);
#789=DIRECTION('',(0.,1.,0.));
#790=VECTOR('',#789,1.);
#791=CARTESIAN_POINT('',(-32.1130814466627,-34.8083763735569,-5.0000000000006));
#792=LINE('',#791,#790);
#793=EDGE_CURVE('E715',#620,#786,#792,.T.);
#794=ORIENTED_EDGE('',*,*,#793,.F.);
#795=ORIENTED_EDGE('',*,*,#621,.F.);
#796=EDGE_LOOP('',(#722,#731,#737,#738,#746,#750,#756,#757,#765,#769,#775,#776,#784,#788,#794,#795));
#797=FACE_BOUND('',#796,.T.);
#798=ORIENTED_EDGE('',*,*,#416,.T.);
#799=EDGE_CURVE('E702',#406,#269,#718,.T.);
#800=ORIENTED_EDGE('',*,*,#799,.T.);
#801=ORIENTED_EDGE('',*,*,#270,.F.);
#802=EDGE_CURVE('E726',#428,#267,#792,.T.);
#803=ORIENTED_EDGE('',*,*,#802,.F.);
#804=ORIENTED_EDGE('',*,*,#431,.T.);
#805=EDGE_CURVE('E757',#430,#361,#780,.T.);
#806=ORIENTED_EDGE('',*,*,#805,.T.);
#807=ORIENTED_EDGE('',*,*,#362,.F.);
#808=CARTESIAN_POINT('',(5.00000000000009,0.,-32.1130814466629));
#809=VERTEX_POINT('',#808);
#810=EDGE_CURVE('E370',#809,#352,#773,.T.);
#811=ORIENTED_EDGE('',*,*,#810,.F.);
#812=CARTESIAN_POINT('',(32.1130814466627,0.,-5.0000000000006));
#813=VERTEX_POINT('',#812);
#814=EDGE_CURVE('E960',#809,#813,#413,.T.);
#815=ORIENTED_EDGE('',*,*,#814,.T.);
#816=EDGE_CURVE('E785',#813,#332,#761,.T.);
#817=ORIENTED_EDGE('',*,*,#816,.T.);
#818=ORIENTED_EDGE('',*,*,#333,.F.);
#819=EDGE_CURVE('E798',#455,#323,#754,.T.);
#820=ORIENTED_EDGE('',*,*,#819,.F.);
#821=ORIENTED_EDGE('',*,*,#458,.T.);
#822=EDGE_CURVE('E820',#457,#303,#742,.T.);
#823=ORIENTED_EDGE('',*,*,#822,.T.);
#824=ORIENTED_EDGE('',*,*,#304,.F.);
#825=EDGE_CURVE('E830',#415,#294,#735,.T.);
#826=ORIENTED_EDGE('',*,*,#825,.F.);
#827=EDGE_LOOP('',(#798,#800,#801,#803,#804,#806,#807,#811,#815,#817,#818,#820,#821,#823,#824,#826));
#828=FACE_BOUND('',#827,.T.);
#829=ADVANCED_FACE('F589',(#797,#828),#714,.T.);
#830=DIRECTION('',(0.,1.,0.));
#831=VECTOR('',#830,1.);
#832=CARTESIAN_POINT('',(5.00000000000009,-34.8083763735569,-34.6410161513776));
#833=LINE('',#832,#831);
#834=CARTESIAN_POINT('',(5.00000000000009,21.9,-34.6410161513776));
#835=VERTEX_POINT('',#834);
#836=EDGE_CURVE('E742',#188,#835,#833,.T.);
#837=ORIENTED_EDGE('',*,*,#836,.T.);
#838=CARTESIAN_POINT('',(0.,21.9,0.));
#839=DIRECTION('',(0.,1.,0.));
#840=DIRECTION('',(0.,0.,1.));
#841=AXIS2_PLACEMENT_3D('',#838,#839,#840);
#842=CIRCLE('',#841,35.);
#843=CARTESIAN_POINT('',(34.6410161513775,21.9,-5.0000000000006));
#844=VERTEX_POINT('',#843);
#845=EDGE_CURVE('E381',#835,#844,#842,.F.);
#846=ORIENTED_EDGE('',*,*,#845,.T.);
#847=DIRECTION('',(0.,1.,0.));
#848=VECTOR('',#847,1.);
#849=CARTESIAN_POINT('',(34.6410161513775,-34.8083763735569,-5.0000000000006));
#850=LINE('',#849,#848);
#851=EDGE_CURVE('E790',#192,#844,#850,.T.);
#852=ORIENTED_EDGE('',*,*,#851,.F.);
#853=ORIENTED_EDGE('',*,*,#193,.T.);
#854=EDGE_LOOP('',(#837,#846,#852,#853));
#855=FACE_BOUND('',#854,.T.);
#856=ADVANCED_FACE('F593',(#855),#23,.T.);
#857=CARTESIAN_POINT('',(0.,13.2647697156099,0.));
#858=DIRECTION('',(0.,1.,0.));
#859=DIRECTION('',(0.,0.,1.));
#860=AXIS2_PLACEMENT_3D('',#857,#858,#859);
#861=CYLINDRICAL_SURFACE('',#860,25.);
#862=ORIENTED_EDGE('',*,*,#137,.F.);
#863=EDGE_LOOP('',(#862));
#864=FACE_BOUND('',#863,.T.);
#865=ORIENTED_EDGE('',*,*,#257,.T.);
#866=EDGE_LOOP('',(#865));
#867=FACE_BOUND('',#866,.T.);
#868=ADVANCED_FACE('F605',(#864,#867),#861,.T.);
#869=ORIENTED_EDGE('',*,*,#814,.F.);
#870=DIRECTION('',(0.,0.,-1.));
#871=VECTOR('',#870,1.);
#872=CARTESIAN_POINT('',(5.00000000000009,0.,0.));
#873=LINE('',#872,#871);
#874=CARTESIAN_POINT('',(5.00000000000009,0.,-34.6410161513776));
#875=VERTEX_POINT('',#874);
#876=EDGE_CURVE('E893',#809,#875,#873,.T.);
#877=ORIENTED_EDGE('',*,*,#876,.T.);
#878=CARTESIAN_POINT('',(34.6410161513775,0.,-5.0000000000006));
#879=VERTEX_POINT('',#878);
#880=EDGE_CURVE('E988',#879,#875,#394,.T.);
#881=ORIENTED_EDGE('',*,*,#880,.F.);
#882=DIRECTION('',(-1.,0.,0.));
#883=VECTOR('',#882,1.);
#884=CARTESIAN_POINT('',(0.,0.,-5.0000000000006));
#885=LINE('',#884,#883);
#886=EDGE_CURVE('E869',#879,#813,#885,.T.);
#887=ORIENTED_EDGE('',*,*,#886,.T.);
#888=EDGE_LOOP('',(#869,#877,#881,#887));
#889=FACE_BOUND('',#888,.T.);
#890=ADVANCED_FACE('F607',(#889),#389,.F.);
#891=ORIENTED_EDGE('',*,*,#880,.T.);
#892=EDGE_CURVE('E751',#875,#344,#833,.T.);
#893=ORIENTED_EDGE('',*,*,#892,.T.);
#894=ORIENTED_EDGE('',*,*,#345,.F.);
#895=EDGE_CURVE('E789',#879,#340,#850,.T.);
#896=ORIENTED_EDGE('',*,*,#895,.F.);
#897=EDGE_LOOP('',(#891,#893,#894,#896));
#898=FACE_BOUND('',#897,.T.);
#899=ADVANCED_FACE('F451',(#898),#23,.T.);
#900=CARTESIAN_POINT('',(5.00000000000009,-14.7,-34.6410161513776));
#901=VERTEX_POINT('',#900);
#902=EDGE_CURVE('E747',#652,#901,#833,.T.);
#903=ORIENTED_EDGE('',*,*,#902,.T.);
#904=CARTESIAN_POINT('',(0.,-14.7,0.));
#905=DIRECTION('',(0.,-1.,0.));
#906=DIRECTION('',(0.,0.,-1.));
#907=AXIS2_PLACEMENT_3D('',#904,#905,#906);
#908=CIRCLE('',#907,35.);
#909=CARTESIAN_POINT('',(34.6410161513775,-14.7,-5.0000000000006));
#910=VERTEX_POINT('',#909);
#911=EDGE_CURVE('E438',#901,#910,#908,.T.);
#912=ORIENTED_EDGE('',*,*,#911,.T.);
#913=EDGE_CURVE('E781',#656,#910,#850,.T.);
#914=ORIENTED_EDGE('',*,*,#913,.F.);
#915=ORIENTED_EDGE('',*,*,#657,.F.);
#916=EDGE_LOOP('',(#903,#912,#914,#915));
#917=FACE_BOUND('',#916,.T.);
#918=ADVANCED_FACE('F578',(#917),#512,.T.);
#919=CARTESIAN_POINT('',(5.00000000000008,-34.8083763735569,34.6410161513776));
#920=DIRECTION('',(1.,0.,0.));
#921=DIRECTION('',(0.,0.,-1.));
#922=AXIS2_PLACEMENT_3D('',#919,#920,#921);
#923=PLANE('',#922);
#924=ORIENTED_EDGE('',*,*,#583,.T.);
#925=CARTESIAN_POINT('',(5.00000000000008,-14.7,34.6410161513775));
#926=CARTESIAN_POINT('',(5.00000000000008,-14.2831580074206,34.2198670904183));
#927=CARTESIAN_POINT('',(5.00000000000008,-13.8664036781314,33.7986313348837));
#928=CARTESIAN_POINT('',(5.00000000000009,-13.0330703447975,32.9559864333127));
#929=CARTESIAN_POINT('',(5.00000000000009,-12.6164913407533,32.5345772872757));
#930=CARTESIAN_POINT('',(5.00000000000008,-12.2,32.1130814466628));
#931=B_SPLINE_CURVE_WITH_KNOTS('',3,(#925,#926,#927,#928,#929,#930),.UNSPECIFIED.,.F.,.F.,(4,2,
4),(0.,1.77767083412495,3.55534167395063),.UNSPECIFIED.);
#932=EDGE_CURVE('E533',#578,#744,#931,.T.);
#933=ORIENTED_EDGE('',*,*,#932,.T.);
#934=ORIENTED_EDGE('',*,*,#745,.F.);
#935=ORIENTED_EDGE('',*,*,#689,.F.);
#936=EDGE_LOOP('',(#924,#933,#934,#935));
#937=FACE_BOUND('',#936,.T.);
#938=ADVANCED_FACE('F582',(#937),#923,.F.);
#939=CARTESIAN_POINT('',(-5.00000000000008,-34.8083763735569,32.1130814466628));
#940=DIRECTION('',(-1.,0.,0.));
#941=DIRECTION('',(0.,0.,1.));
#942=AXIS2_PLACEMENT_3D('',#939,#940,#941);
#943=PLANE('',#942);
#944=ORIENTED_EDGE('',*,*,#736,.T.);
#945=CARTESIAN_POINT('',(-5.00000000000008,-12.2,32.1130814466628));
#946=CARTESIAN_POINT('',(-5.00000000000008,-12.6164913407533,32.5345772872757));
#947=CARTESIAN_POINT('',(-5.00000000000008,-13.0330703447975,32.9559864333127));
#948=CARTESIAN_POINT('',(-5.00000000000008,-13.8664036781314,33.7986313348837));
#949=CARTESIAN_POINT('',(-5.00000000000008,-14.2831580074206,34.2198670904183));
#950=CARTESIAN_POINT('',(-5.00000000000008,-14.7,34.6410161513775));
#951=B_SPLINE_CURVE_WITH_KNOTS('',3,(#945,#946,#947,#948,#949,#950),.UNSPECIFIED.,.F.,.F.,(4,2,
4),(0.,1.77767083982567,3.55534167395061),.UNSPECIFIED.);
#952=EDGE_CURVE('E559',#729,#516,#951,.T.);
#953=ORIENTED_EDGE('',*,*,#952,.T.);
#954=ORIENTED_EDGE('',*,*,#517,.F.);
#955=ORIENTED_EDGE('',*,*,#704,.F.);
#956=EDGE_LOOP('',(#944,#953,#954,#955));
#957=FACE_BOUND('',#956,.T.);
#958=ADVANCED_FACE('F576',(#957),#943,.F.);
#959=CARTESIAN_POINT('',(32.1130814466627,-34.8083763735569,-5.0000000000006));
#960=DIRECTION('',(0.,0.,-1.));
#961=DIRECTION('',(-1.,0.,0.));
#962=AXIS2_PLACEMENT_3D('',#959,#960,#961);
#963=PLANE('',#962);
#964=ORIENTED_EDGE('',*,*,#913,.T.);
#965=CARTESIAN_POINT('',(34.6410161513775,-14.7,-5.0000000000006));
#966=CARTESIAN_POINT('',(34.2198670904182,-14.2831580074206,-5.0000000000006));
#967=CARTESIAN_POINT('',(33.7986313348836,-13.8664036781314,-5.0000000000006));
#968=CARTESIAN_POINT('',(32.9559864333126,-13.0330703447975,-5.0000000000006));
#969=CARTESIAN_POINT('',(32.5345772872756,-12.6164913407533,-5.0000000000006));
#970=CARTESIAN_POINT('',(32.1130814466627,-12.2,-5.0000000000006));
#971=B_SPLINE_CURVE_WITH_KNOTS('',3,(#965,#966,#967,#968,#969,#970),.UNSPECIFIED.,.F.,.F.,(4,2,
4),(0.,1.77767083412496,3.55534167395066),.UNSPECIFIED.);
#972=EDGE_CURVE('E458',#910,#763,#971,.T.);
#973=ORIENTED_EDGE('',*,*,#972,.T.);
#974=ORIENTED_EDGE('',*,*,#764,.F.);
#975=ORIENTED_EDGE('',*,*,#665,.F.);
#976=EDGE_LOOP('',(#964,#973,#974,#975));
#977=FACE_BOUND('',#976,.T.);
#978=ADVANCED_FACE('F513',(#977),#963,.F.);
#979=CARTESIAN_POINT('',(34.6410161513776,-34.8083763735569,5.00000000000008));
#980=DIRECTION('',(0.,0.,1.));
#981=DIRECTION('',(1.,0.,0.));
#982=AXIS2_PLACEMENT_3D('',#979,#980,#981);
#983=PLANE('',#982);
#984=ORIENTED_EDGE('',*,*,#755,.T.);
#985=CARTESIAN_POINT('',(32.1130814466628,-12.2,5.00000000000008));
#986=CARTESIAN_POINT('',(32.5345772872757,-12.6164913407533,5.00000000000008));
#987=CARTESIAN_POINT('',(32.9559864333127,-13.0330703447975,5.00000000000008));
#988=CARTESIAN_POINT('',(33.7986313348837,-13.8664036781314,5.00000000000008));
#989=CARTESIAN_POINT('',(34.2198670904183,-14.2831580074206,5.00000000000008));
#990=CARTESIAN_POINT('',(34.6410161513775,-14.7,5.00000000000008));
#991=B_SPLINE_CURVE_WITH_KNOTS('',3,(#985,#986,#987,#988,#989,#990),.UNSPECIFIED.,.F.,.F.,(4,2,
4),(0.,1.77767083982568,3.55534167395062),.UNSPECIFIED.);
#992=EDGE_CURVE('E525',#748,#569,#991,.T.);
#993=ORIENTED_EDGE('',*,*,#992,.T.);
#994=ORIENTED_EDGE('',*,*,#570,.F.);
#995=ORIENTED_EDGE('',*,*,#680,.F.);
#996=EDGE_LOOP('',(#984,#993,#994,#995));
#997=FACE_BOUND('',#996,.T.);
#998=ADVANCED_FACE('F521',(#997),#983,.F.);
#999=CARTESIAN_POINT('',(5.00000000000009,-34.8083763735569,-32.1130814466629));
#1000=DIRECTION('',(1.,0.,0.));
#1001=DIRECTION('',(0.,0.,-1.));
#1002=AXIS2_PLACEMENT_3D('',#999,#1000,#1001);
#1003=PLANE('',#1002);
#1004=ORIENTED_EDGE('',*,*,#774,.T.);
#1005=CARTESIAN_POINT('',(5.00000000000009,-12.2,-32.1130814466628));
#1006=CARTESIAN_POINT('',(5.00000000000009,-12.6164913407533,-32.5345772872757));
#1007=CARTESIAN_POINT('',(5.00000000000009,-13.0330703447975,-32.9559864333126));
#1008=CARTESIAN_POINT('',(5.00000000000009,-13.8664036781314,-33.7986313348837));
#1009=CARTESIAN_POINT('',(5.00000000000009,-14.2831580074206,-34.2198670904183));
#1010=CARTESIAN_POINT('',(5.00000000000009,-14.7,-34.6410161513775));
#1011=B_SPLINE_CURVE_WITH_KNOTS('',3,(#1005,#1006,#1007,#1008,#1009,#1010),.UNSPECIFIED.,.F.,
.F.,(4,2,4),(0.,1.77767083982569,3.55534167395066),.UNSPECIFIED.);
#1012=EDGE_CURVE('E464',#767,#901,#1011,.T.);
#1013=ORIENTED_EDGE('',*,*,#1012,.T.);
#1014=ORIENTED_EDGE('',*,*,#902,.F.);
#1015=ORIENTED_EDGE('',*,*,#653,.F.);
#1016=EDGE_LOOP('',(#1004,#1013,#1014,#1015));
#1017=FACE_BOUND('',#1016,.T.);
#1018=ADVANCED_FACE('F475',(#1017),#1003,.F.);
#1019=CARTESIAN_POINT('',(-5.00000000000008,-34.8083763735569,-34.6410161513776));
#1020=DIRECTION('',(-1.,0.,0.));
#1021=DIRECTION('',(0.,0.,1.));
#1022=AXIS2_PLACEMENT_3D('',#1019,#1020,#1021);
#1023=PLANE('',#1022);
#1024=ORIENTED_EDGE('',*,*,#559,.T.);
#1025=CARTESIAN_POINT('',(-5.00000000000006,-14.7,-34.6410161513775));
#1026=CARTESIAN_POINT('',(-5.00000000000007,-14.2831580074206,-34.2198670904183));
#1027=CARTESIAN_POINT('',(-5.00000000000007,-13.8664036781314,-33.7986313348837));
#1028=CARTESIAN_POINT('',(-5.00000000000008,-13.0330703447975,-32.9559864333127));
#1029=CARTESIAN_POINT('',(-5.00000000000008,-12.6164913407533,-32.5345772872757));
#1030=CARTESIAN_POINT('',(-5.00000000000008,-12.2,-32.1130814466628));
#1031=B_SPLINE_CURVE_WITH_KNOTS('',3,(#1025,#1026,#1027,#1028,#1029,#1030),.UNSPECIFIED.,.F.,
.F.,(4,2,4),(0.,1.77767083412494,3.55534167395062),.UNSPECIFIED.);
#1032=EDGE_CURVE('E439',#554,#782,#1031,.T.);
#1033=ORIENTED_EDGE('',*,*,#1032,.T.);
#1034=ORIENTED_EDGE('',*,*,#783,.F.);
#1035=ORIENTED_EDGE('',*,*,#636,.F.);
#1036=EDGE_LOOP('',(#1024,#1033,#1034,#1035));
#1037=FACE_BOUND('',#1036,.T.);
#1038=ADVANCED_FACE('F1006',(#1037),#1023,.F.);
#1039=CARTESIAN_POINT('',(-34.6410161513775,-34.8083763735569,-5.0000000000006));
#1040=DIRECTION('',(0.,0.,-1.));
#1041=DIRECTION('',(-1.,0.,0.));
#1042=AXIS2_PLACEMENT_3D('',#1039,#1040,#1041);
#1043=PLANE('',#1042);
#1044=ORIENTED_EDGE('',*,*,#793,.T.);
#1045=CARTESIAN_POINT('',(-32.1130814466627,-12.2,-5.0000000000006));
#1046=CARTESIAN_POINT('',(-32.5345772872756,-12.6164913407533,-5.0000000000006));
#1047=CARTESIAN_POINT('',(-32.9559864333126,-13.0330703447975,-5.0000000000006));
#1048=CARTESIAN_POINT('',(-33.7986313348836,-13.8664036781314,-5.0000000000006));
#1049=CARTESIAN_POINT('',(-34.2198670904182,-14.2831580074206,-5.0000000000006));
#1050=CARTESIAN_POINT('',(-34.6410161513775,-14.7,-5.0000000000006));
#1051=B_SPLINE_CURVE_WITH_KNOTS('',3,(#1045,#1046,#1047,#1048,#1049,#1050),.UNSPECIFIED.,.F.,
.F.,(4,2,4),(0.,1.77767083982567,3.55534167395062),.UNSPECIFIED.);
#1052=EDGE_CURVE('E430',#786,#545,#1051,.T.);
#1053=ORIENTED_EDGE('',*,*,#1052,.T.);
#1054=ORIENTED_EDGE('',*,*,#546,.F.);
#1055=ORIENTED_EDGE('',*,*,#627,.F.);
#1056=EDGE_LOOP('',(#1044,#1053,#1054,#1055));
#1057=FACE_BOUND('',#1056,.T.);
#1058=ADVANCED_FACE('F424',(#1057),#1043,.F.);
#1059=CARTESIAN_POINT('',(-32.1130814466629,-34.8083763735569,4.9999999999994));
#1060=DIRECTION('',(0.,0.,1.));
#1061=DIRECTION('',(1.,0.,0.));
#1062=AXIS2_PLACEMENT_3D('',#1059,#1060,#1061);
#1063=PLANE('',#1062);
#1064=ORIENTED_EDGE('',*,*,#530,.T.);
#1065=CARTESIAN_POINT('',(-34.6410161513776,-14.7,4.9999999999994));
#1066=CARTESIAN_POINT('',(-34.2198670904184,-14.2831580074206,4.9999999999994));
#1067=CARTESIAN_POINT('',(-33.7986313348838,-13.8664036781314,4.9999999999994));
#1068=CARTESIAN_POINT('',(-32.9559864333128,-13.0330703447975,4.9999999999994));
#1069=CARTESIAN_POINT('',(-32.5345772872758,-12.6164913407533,4.9999999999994));
#1070=CARTESIAN_POINT('',(-32.1130814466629,-12.2,4.9999999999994));
#1071=B_SPLINE_CURVE_WITH_KNOTS('',3,(#1065,#1066,#1067,#1068,#1069,#1070),.UNSPECIFIED.,.F.,
.F.,(4,2,4),(0.,1.77767083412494,3.55534167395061),.UNSPECIFIED.);
#1072=EDGE_CURVE('E554',#525,#720,#1071,.T.);
#1073=ORIENTED_EDGE('',*,*,#1072,.T.);
#1074=ORIENTED_EDGE('',*,*,#721,.F.);
#1075=ORIENTED_EDGE('',*,*,#612,.F.);
#1076=EDGE_LOOP('',(#1064,#1073,#1074,#1075));
#1077=FACE_BOUND('',#1076,.T.);
#1078=ADVANCED_FACE('F1042',(#1077),#1063,.F.);
#1079=ORIENTED_EDGE('',*,*,#822,.F.);
#1080=ORIENTED_EDGE('',*,*,#476,.F.);
#1081=ORIENTED_EDGE('',*,*,#503,.T.);
#1082=ORIENTED_EDGE('',*,*,#312,.F.);
#1083=EDGE_LOOP('',(#1079,#1080,#1081,#1082));
#1084=FACE_BOUND('',#1083,.T.);
#1085=ADVANCED_FACE('F1058',(#1084),#923,.F.);
#1086=ORIENTED_EDGE('',*,*,#485,.F.);
#1087=ORIENTED_EDGE('',*,*,#422,.F.);
#1088=ORIENTED_EDGE('',*,*,#825,.T.);
#1089=ORIENTED_EDGE('',*,*,#295,.F.);
#1090=EDGE_LOOP('',(#1086,#1087,#1088,#1089));
#1091=FACE_BOUND('',#1090,.T.);
#1092=ADVANCED_FACE('F575',(#1091),#943,.F.);
#1093=ORIENTED_EDGE('',*,*,#816,.F.);
#1094=ORIENTED_EDGE('',*,*,#886,.F.);
#1095=ORIENTED_EDGE('',*,*,#895,.T.);
#1096=ORIENTED_EDGE('',*,*,#341,.F.);
#1097=EDGE_LOOP('',(#1093,#1094,#1095,#1096));
#1098=FACE_BOUND('',#1097,.T.);
#1099=ADVANCED_FACE('F512',(#1098),#963,.F.);
#1100=ORIENTED_EDGE('',*,*,#500,.F.);
#1101=ORIENTED_EDGE('',*,*,#466,.F.);
#1102=ORIENTED_EDGE('',*,*,#819,.T.);
#1103=ORIENTED_EDGE('',*,*,#324,.F.);
#1104=EDGE_LOOP('',(#1100,#1101,#1102,#1103));
#1105=FACE_BOUND('',#1104,.T.);
#1106=ADVANCED_FACE('F520',(#1105),#983,.F.);
#1107=ORIENTED_EDGE('',*,*,#805,.F.);
#1108=ORIENTED_EDGE('',*,*,#449,.F.);
#1109=ORIENTED_EDGE('',*,*,#494,.T.);
#1110=ORIENTED_EDGE('',*,*,#370,.F.);
#1111=EDGE_LOOP('',(#1107,#1108,#1109,#1110));
#1112=FACE_BOUND('',#1111,.T.);
#1113=ADVANCED_FACE('F1176',(#1112),#1023,.F.);
#1114=ORIENTED_EDGE('',*,*,#892,.F.);
#1115=ORIENTED_EDGE('',*,*,#876,.F.);
#1116=ORIENTED_EDGE('',*,*,#810,.T.);
#1117=ORIENTED_EDGE('',*,*,#353,.F.);
#1118=EDGE_LOOP('',(#1114,#1115,#1116,#1117));
#1119=FACE_BOUND('',#1118,.T.);
#1120=ADVANCED_FACE('F474',(#1119),#1003,.F.);
#1121=ORIENTED_EDGE('',*,*,#799,.F.);
#1122=ORIENTED_EDGE('',*,*,#407,.F.);
#1123=ORIENTED_EDGE('',*,*,#482,.T.);
#1124=ORIENTED_EDGE('',*,*,#278,.F.);
#1125=EDGE_LOOP('',(#1121,#1122,#1123,#1124));
#1126=FACE_BOUND('',#1125,.T.);
#1127=ADVANCED_FACE('F1188',(#1126),#1063,.F.);
#1128=ORIENTED_EDGE('',*,*,#491,.F.);
#1129=ORIENTED_EDGE('',*,*,#439,.F.);
#1130=ORIENTED_EDGE('',*,*,#802,.T.);
#1131=ORIENTED_EDGE('',*,*,#380,.F.);
#1132=EDGE_LOOP('',(#1128,#1129,#1130,#1131));
#1133=FACE_BOUND('',#1132,.T.);
#1134=ADVANCED_FACE('F423',(#1133),#1043,.F.);
#1135=CARTESIAN_POINT('',(-5.00000000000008,24.4,32.1130814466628));
#1136=VERTEX_POINT('',#1135);
#1137=EDGE_CURVE('E810',#233,#1136,#735,.T.);
#1138=ORIENTED_EDGE('',*,*,#1137,.T.);
#1139=CARTESIAN_POINT('',(-5.00000000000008,24.4,32.1130814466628));
#1140=CARTESIAN_POINT('',(-5.00000000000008,23.9835086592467,32.5345772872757));
#1141=CARTESIAN_POINT('',(-5.00000000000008,23.5669296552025,32.9559864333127));
#1142=CARTESIAN_POINT('',(-5.00000000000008,22.7335963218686,33.7986313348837));
#1143=CARTESIAN_POINT('',(-5.00000000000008,22.3168419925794,34.2198670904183));
#1144=CARTESIAN_POINT('',(-5.00000000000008,21.9,34.6410161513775));
#1145=B_SPLINE_CURVE_WITH_KNOTS('',3,(#1139,#1140,#1141,#1142,#1143,#1144),.UNSPECIFIED.,.F.,
.F.,(4,2,4),(0.,1.77767083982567,3.55534167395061),.UNSPECIFIED.);
#1146=EDGE_CURVE('E63',#1136,#31,#1145,.T.);
#1147=ORIENTED_EDGE('',*,*,#1146,.T.);
#1148=ORIENTED_EDGE('',*,*,#32,.F.);
#1149=ORIENTED_EDGE('',*,*,#240,.F.);
#1150=EDGE_LOOP('',(#1138,#1147,#1148,#1149));
#1151=FACE_BOUND('',#1150,.T.);
#1152=ADVANCED_FACE('F570',(#1151),#943,.F.);
#1153=ORIENTED_EDGE('',*,*,#118,.T.);
#1154=CARTESIAN_POINT('',(5.00000000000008,21.9,34.6410161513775));
#1155=CARTESIAN_POINT('',(5.00000000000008,22.3168419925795,34.2198670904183));
#1156=CARTESIAN_POINT('',(5.00000000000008,22.7335963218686,33.7986313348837));
#1157=CARTESIAN_POINT('',(5.00000000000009,23.5669296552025,32.9559864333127));
#1158=CARTESIAN_POINT('',(5.00000000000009,23.9835086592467,32.5345772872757));
#1159=CARTESIAN_POINT('',(5.00000000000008,24.4,32.1130814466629));
#1160=B_SPLINE_CURVE_WITH_KNOTS('',3,(#1154,#1155,#1156,#1157,#1158,#1159),.UNSPECIFIED.,.F.,
.F.,(4,2,4),(0.,1.77767083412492,3.55534167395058),.UNSPECIFIED.);
#1161=CARTESIAN_POINT('',(5.00000000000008,24.4,32.1130814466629));
#1162=VERTEX_POINT('',#1161);
#1163=EDGE_CURVE('E1145',#109,#1162,#1160,.T.);
#1164=ORIENTED_EDGE('',*,*,#1163,.T.);
#1165=EDGE_CURVE('E815',#224,#1162,#742,.T.);
#1166=ORIENTED_EDGE('',*,*,#1165,.F.);
#1167=ORIENTED_EDGE('',*,*,#225,.F.);
#1168=EDGE_LOOP('',(#1153,#1164,#1166,#1167));
#1169=FACE_BOUND('',#1168,.T.);
#1170=ADVANCED_FACE('F574',(#1169),#923,.F.);
#1171=CARTESIAN_POINT('',(0.,-34.8083763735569,0.));
#1172=DIRECTION('',(0.,1.,0.));
#1173=DIRECTION('',(0.,0.,1.));
#1174=AXIS2_PLACEMENT_3D('',#1171,#1172,#1173);
#1175=CYLINDRICAL_SURFACE('',#1174,32.5);
#1176=ORIENTED_EDGE('',*,*,#1165,.T.);
#1177=CARTESIAN_POINT('',(0.,24.4,0.));
#1178=DIRECTION('',(0.,-1.,0.));
#1179=DIRECTION('',(0.,0.,1.));
#1180=AXIS2_PLACEMENT_3D('',#1177,#1178,#1179);
#1181=CIRCLE('',#1180,32.5);
#1182=EDGE_CURVE('E799',#1162,#1136,#1181,.T.);
#1183=ORIENTED_EDGE('',*,*,#1182,.T.);
#1184=ORIENTED_EDGE('',*,*,#1137,.F.);
#1185=ORIENTED_EDGE('',*,*,#234,.F.);
#1186=EDGE_LOOP('',(#1176,#1183,#1184,#1185));
#1187=FACE_BOUND('',#1186,.T.);
#1188=ADVANCED_FACE('F518',(#1187),#1175,.T.);
#1189=CARTESIAN_POINT('',(32.1130814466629,24.4,5.00000000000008));
#1190=VERTEX_POINT('',#1189);
#1191=EDGE_CURVE('E774',#209,#1190,#754,.T.);
#1192=ORIENTED_EDGE('',*,*,#1191,.T.);
#1193=CARTESIAN_POINT('',(32.1130814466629,24.4,5.00000000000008));
#1194=CARTESIAN_POINT('',(32.5345772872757,23.9835086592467,5.00000000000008));
#1195=CARTESIAN_POINT('',(32.9559864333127,23.5669296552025,5.00000000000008));
#1196=CARTESIAN_POINT('',(33.7986313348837,22.7335963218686,5.00000000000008));
#1197=CARTESIAN_POINT('',(34.2198670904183,22.3168419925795,5.00000000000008));
#1198=CARTESIAN_POINT('',(34.6410161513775,21.9,5.00000000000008));
#1199=B_SPLINE_CURVE_WITH_KNOTS('',3,(#1193,#1194,#1195,#1196,#1197,#1198),.UNSPECIFIED.,.F.,
.F.,(4,2,4),(0.,1.77767083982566,3.55534167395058),.UNSPECIFIED.);
#1200=EDGE_CURVE('E499',#1190,#100,#1199,.T.);
#1201=ORIENTED_EDGE('',*,*,#1200,.T.);
#1202=ORIENTED_EDGE('',*,*,#101,.F.);
#1203=ORIENTED_EDGE('',*,*,#216,.F.);
#1204=EDGE_LOOP('',(#1192,#1201,#1202,#1203));
#1205=FACE_BOUND('',#1204,.T.);
#1206=ADVANCED_FACE('F510',(#1205),#983,.F.);
#1207=ORIENTED_EDGE('',*,*,#851,.T.);
#1208=CARTESIAN_POINT('',(34.6410161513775,21.9,-5.0000000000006));
#1209=CARTESIAN_POINT('',(34.2198670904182,22.3168419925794,-5.0000000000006));
#1210=CARTESIAN_POINT('',(33.7986313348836,22.7335963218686,-5.0000000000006));
#1211=CARTESIAN_POINT('',(32.9559864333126,23.5669296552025,-5.0000000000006));
#1212=CARTESIAN_POINT('',(32.5345772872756,23.9835086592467,-5.0000000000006));
#1213=CARTESIAN_POINT('',(32.1130814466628,24.4,-5.0000000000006));
#1214=B_SPLINE_CURVE_WITH_KNOTS('',3,(#1208,#1209,#1210,#1211,#1212,#1213),.UNSPECIFIED.,.F.,
.F.,(4,2,4),(0.,1.77767083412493,3.5553416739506),.UNSPECIFIED.);
#1215=CARTESIAN_POINT('',(32.1130814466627,24.4,-5.0000000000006));
#1216=VERTEX_POINT('',#1215);
#1217=EDGE_CURVE('E493',#844,#1216,#1214,.T.);
#1218=ORIENTED_EDGE('',*,*,#1217,.T.);
#1219=EDGE_CURVE('E780',#200,#1216,#761,.T.);
#1220=ORIENTED_EDGE('',*,*,#1219,.F.);
#1221=ORIENTED_EDGE('',*,*,#201,.F.);
#1222=EDGE_LOOP('',(#1207,#1218,#1220,#1221));
#1223=FACE_BOUND('',#1222,.T.);
#1224=ADVANCED_FACE('F505',(#1223),#963,.F.);
#1225=CARTESIAN_POINT('',(0.,-34.8083763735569,0.));
#1226=DIRECTION('',(0.,1.,0.));
#1227=DIRECTION('',(0.,0.,1.));
#1228=AXIS2_PLACEMENT_3D('',#1225,#1226,#1227);
#1229=CYLINDRICAL_SURFACE('',#1228,32.5);
#1230=ORIENTED_EDGE('',*,*,#1219,.T.);
#1231=CARTESIAN_POINT('',(0.,24.4,0.));
#1232=DIRECTION('',(0.,-1.,0.));
#1233=DIRECTION('',(0.,0.,1.));
#1234=AXIS2_PLACEMENT_3D('',#1231,#1232,#1233);
#1235=CIRCLE('',#1234,32.5);
#1236=EDGE_CURVE('E388',#1216,#1190,#1235,.T.);
#1237=ORIENTED_EDGE('',*,*,#1236,.T.);
#1238=ORIENTED_EDGE('',*,*,#1191,.F.);
#1239=ORIENTED_EDGE('',*,*,#210,.F.);
#1240=EDGE_LOOP('',(#1230,#1237,#1238,#1239));
#1241=FACE_BOUND('',#1240,.T.);
#1242=ADVANCED_FACE('F509',(#1241),#1229,.T.);
#1243=ORIENTED_EDGE('',*,*,#86,.T.);
#1244=CARTESIAN_POINT('',(-5.00000000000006,21.9,-34.6410161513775));
#1245=CARTESIAN_POINT('',(-5.00000000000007,22.3168419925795,-34.2198670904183));
#1246=CARTESIAN_POINT('',(-5.00000000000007,22.7335963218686,-33.7986313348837));
#1247=CARTESIAN_POINT('',(-5.00000000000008,23.5669296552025,-32.9559864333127));
#1248=CARTESIAN_POINT('',(-5.00000000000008,23.9835086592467,-32.5345772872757));
#1249=CARTESIAN_POINT('',(-5.00000000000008,24.4,-32.1130814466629));
#1250=B_SPLINE_CURVE_WITH_KNOTS('',3,(#1244,#1245,#1246,#1247,#1248,#1249),.UNSPECIFIED.,.F.,
.F.,(4,2,4),(0.,1.77767083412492,3.55534167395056),.UNSPECIFIED.);
#1251=CARTESIAN_POINT('',(-5.00000000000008,24.4,-32.1130814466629));
#1252=VERTEX_POINT('',#1251);
#1253=EDGE_CURVE('E383',#77,#1252,#1250,.T.);
#1254=ORIENTED_EDGE('',*,*,#1253,.T.);
#1255=EDGE_CURVE('E353',#171,#1252,#780,.T.);
#1256=ORIENTED_EDGE('',*,*,#1255,.F.);
#1257=ORIENTED_EDGE('',*,*,#172,.F.);
#1258=EDGE_LOOP('',(#1243,#1254,#1256,#1257));
#1259=FACE_BOUND('',#1258,.T.);
#1260=ADVANCED_FACE('F1172',(#1259),#1023,.F.);
#1261=CARTESIAN_POINT('',(0.,-34.8083763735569,0.));
#1262=DIRECTION('',(0.,1.,0.));
#1263=DIRECTION('',(0.,0.,1.));
#1264=AXIS2_PLACEMENT_3D('',#1261,#1262,#1263);
#1265=CYLINDRICAL_SURFACE('',#1264,32.5000000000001);
#1266=ORIENTED_EDGE('',*,*,#1255,.T.);
#1267=CARTESIAN_POINT('',(0.,24.4,0.));
#1268=DIRECTION('',(0.,-1.,0.));
#1269=DIRECTION('',(0.,0.,1.));
#1270=AXIS2_PLACEMENT_3D('',#1267,#1268,#1269);
#1271=CIRCLE('',#1270,32.5000000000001);
#1272=CARTESIAN_POINT('',(5.00000000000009,24.4,-32.1130814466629));
#1273=VERTEX_POINT('',#1272);
#1274=EDGE_CURVE('E347',#1252,#1273,#1271,.T.);
#1275=ORIENTED_EDGE('',*,*,#1274,.T.);
#1276=EDGE_CURVE('E350',#180,#1273,#773,.T.);
#1277=ORIENTED_EDGE('',*,*,#1276,.F.);
#1278=ORIENTED_EDGE('',*,*,#181,.F.);
#1279=EDGE_LOOP('',(#1266,#1275,#1277,#1278));
#1280=FACE_BOUND('',#1279,.T.);
#1281=ADVANCED_FACE('F349',(#1280),#1265,.T.);
#1282=ORIENTED_EDGE('',*,*,#1276,.T.);
#1283=CARTESIAN_POINT('',(5.00000000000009,24.4,-32.1130814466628));
#1284=CARTESIAN_POINT('',(5.00000000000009,23.9835086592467,-32.5345772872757));
#1285=CARTESIAN_POINT('',(5.00000000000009,23.5669296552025,-32.9559864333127));
#1286=CARTESIAN_POINT('',(5.00000000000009,22.7335963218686,-33.7986313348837));
#1287=CARTESIAN_POINT('',(5.00000000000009,22.3168419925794,-34.2198670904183));
#1288=CARTESIAN_POINT('',(5.00000000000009,21.9,-34.6410161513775));
#1289=B_SPLINE_CURVE_WITH_KNOTS('',3,(#1283,#1284,#1285,#1286,#1287,#1288),.UNSPECIFIED.,.F.,
.F.,(4,2,4),(0.,1.77767083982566,3.55534167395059),.UNSPECIFIED.);
#1290=EDGE_CURVE('E365',#1273,#835,#1289,.T.);
#1291=ORIENTED_EDGE('',*,*,#1290,.T.);
#1292=ORIENTED_EDGE('',*,*,#836,.F.);
#1293=ORIENTED_EDGE('',*,*,#189,.F.);
#1294=EDGE_LOOP('',(#1282,#1291,#1292,#1293));
#1295=FACE_BOUND('',#1294,.T.);
#1296=ADVANCED_FACE('F364',(#1295),#1003,.F.);
#1297=ORIENTED_EDGE('',*,*,#49,.T.);
#1298=CARTESIAN_POINT('',(-34.6410161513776,21.9,4.9999999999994));
#1299=CARTESIAN_POINT('',(-34.2198670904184,22.3168419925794,4.9999999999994));
#1300=CARTESIAN_POINT('',(-33.7986313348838,22.7335963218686,4.9999999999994));
#1301=CARTESIAN_POINT('',(-32.9559864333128,23.5669296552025,4.9999999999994));
#1302=CARTESIAN_POINT('',(-32.5345772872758,23.9835086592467,4.9999999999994));
#1303=CARTESIAN_POINT('',(-32.1130814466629,24.4,4.9999999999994));
#1304=B_SPLINE_CURVE_WITH_KNOTS('',3,(#1298,#1299,#1300,#1301,#1302,#1303),.UNSPECIFIED.,.F.,
.F.,(4,2,4),(0.,1.77767083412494,3.5553416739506),.UNSPECIFIED.);
#1305=CARTESIAN_POINT('',(-32.1130814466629,24.4,4.9999999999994));
#1306=VERTEX_POINT('',#1305);
#1307=EDGE_CURVE('E643',#40,#1306,#1304,.T.);
#1308=ORIENTED_EDGE('',*,*,#1307,.T.);
#1309=EDGE_CURVE('E695',#147,#1306,#718,.T.);
#1310=ORIENTED_EDGE('',*,*,#1309,.F.);
#1311=ORIENTED_EDGE('',*,*,#148,.F.);
#1312=EDGE_LOOP('',(#1297,#1308,#1310,#1311));
#1313=FACE_BOUND('',#1312,.T.);
#1314=ADVANCED_FACE('F473',(#1313),#1063,.F.);
#1315=CARTESIAN_POINT('',(0.,-34.8083763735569,0.));
#1316=DIRECTION('',(0.,1.,0.));
#1317=DIRECTION('',(0.,0.,1.));
#1318=AXIS2_PLACEMENT_3D('',#1315,#1316,#1317);
#1319=CYLINDRICAL_SURFACE('',#1318,32.5);
#1320=ORIENTED_EDGE('',*,*,#1309,.T.);
#1321=CARTESIAN_POINT('',(0.,24.4,0.));
#1322=DIRECTION('',(0.,-1.,0.));
#1323=DIRECTION('',(0.,0.,1.));
#1324=AXIS2_PLACEMENT_3D('',#1321,#1322,#1323);
#1325=CIRCLE('',#1324,32.5);
#1326=CARTESIAN_POINT('',(-32.1130814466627,24.4,-5.0000000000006));
#1327=VERTEX_POINT('',#1326);
#1328=EDGE_CURVE('E696',#1306,#1327,#1325,.T.);
#1329=ORIENTED_EDGE('',*,*,#1328,.T.);
#1330=EDGE_CURVE('E718',#156,#1327,#792,.T.);
#1331=ORIENTED_EDGE('',*,*,#1330,.F.);
#1332=ORIENTED_EDGE('',*,*,#157,.F.);
#1333=EDGE_LOOP('',(#1320,#1329,#1331,#1332));
#1334=FACE_BOUND('',#1333,.T.);
#1335=ADVANCED_FACE('F421',(#1334),#1319,.T.);
#1336=ORIENTED_EDGE('',*,*,#1330,.T.);
#1337=CARTESIAN_POINT('',(-32.1130814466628,24.4,-5.0000000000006));
#1338=CARTESIAN_POINT('',(-32.5345772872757,23.9835086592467,-5.0000000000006));
#1339=CARTESIAN_POINT('',(-32.9559864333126,23.5669296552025,-5.0000000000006));
#1340=CARTESIAN_POINT('',(-33.7986313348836,22.7335963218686,-5.0000000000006));
#1341=CARTESIAN_POINT('',(-34.2198670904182,22.3168419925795,-5.0000000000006));
#1342=CARTESIAN_POINT('',(-34.6410161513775,21.9,-5.0000000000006));
#1343=B_SPLINE_CURVE_WITH_KNOTS('',3,(#1337,#1338,#1339,#1340,#1341,#1342),.UNSPECIFIED.,.F.,
.F.,(4,2,4),(0.,1.77767083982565,3.55534167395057),.UNSPECIFIED.);
#1344=EDGE_CURVE('E395',#1327,#68,#1343,.T.);
#1345=ORIENTED_EDGE('',*,*,#1344,.T.);
#1346=ORIENTED_EDGE('',*,*,#69,.F.);
#1347=ORIENTED_EDGE('',*,*,#163,.F.);
#1348=EDGE_LOOP('',(#1336,#1345,#1346,#1347));
#1349=FACE_BOUND('',#1348,.T.);
#1350=ADVANCED_FACE('F415',(#1349),#1043,.F.);
#1351=CARTESIAN_POINT('',(0.,-14.7,0.));
#1352=DIRECTION('',(0.,-1.,0.));
#1353=DIRECTION('',(0.,0.,-1.));
#1354=AXIS2_PLACEMENT_3D('',#1351,#1352,#1353);
#1355=CONICAL_SURFACE('',#1354,35.,0.78539816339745);
#1356=ORIENTED_EDGE('',*,*,#1052,.F.);
#1357=ORIENTED_EDGE('',*,*,#787,.T.);
#1358=ORIENTED_EDGE('',*,*,#1032,.F.);
#1359=ORIENTED_EDGE('',*,*,#555,.F.);
#1360=EDGE_LOOP('',(#1356,#1357,#1358,#1359));
#1361=FACE_BOUND('',#1360,.T.);
#1362=ADVANCED_FACE('F420',(#1361),#1355,.T.);
#1363=CARTESIAN_POINT('',(0.,-14.7,0.));
#1364=DIRECTION('',(0.,-1.,0.));
#1365=DIRECTION('',(0.,0.,-1.));
#1366=AXIS2_PLACEMENT_3D('',#1363,#1364,#1365);
#1367=CONICAL_SURFACE('',#1366,35.,0.785398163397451);
#1368=ORIENTED_EDGE('',*,*,#1012,.F.);
#1369=ORIENTED_EDGE('',*,*,#768,.T.);
#1370=ORIENTED_EDGE('',*,*,#972,.F.);
#1371=ORIENTED_EDGE('',*,*,#911,.F.);
#1372=EDGE_LOOP('',(#1368,#1369,#1370,#1371));
#1373=FACE_BOUND('',#1372,.T.);
#1374=ADVANCED_FACE('F449',(#1373),#1367,.T.);
#1375=CARTESIAN_POINT('',(0.,24.4,0.));
#1376=DIRECTION('',(0.,-1.,0.));
#1377=DIRECTION('',(0.,0.,-1.));
#1378=AXIS2_PLACEMENT_3D('',#1375,#1376,#1377);
#1379=CONICAL_SURFACE('',#1378,32.5000000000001,0.785398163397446);
#1380=ORIENTED_EDGE('',*,*,#1253,.F.);
#1381=ORIENTED_EDGE('',*,*,#78,.F.);
#1382=ORIENTED_EDGE('',*,*,#1344,.F.);
#1383=CARTESIAN_POINT('',(0.,24.4,0.));
#1384=DIRECTION('',(0.,1.,0.));
#1385=DIRECTION('',(0.,0.,1.));
#1386=AXIS2_PLACEMENT_3D('',#1383,#1384,#1385);
#1387=CIRCLE('',#1386,32.5000000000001);
#1388=EDGE_CURVE('E390',#1252,#1327,#1387,.T.);
#1389=ORIENTED_EDGE('',*,*,#1388,.F.);
#1390=EDGE_LOOP('',(#1380,#1381,#1382,#1389));
#1391=FACE_BOUND('',#1390,.T.);
#1392=ADVANCED_FACE('F411',(#1391),#1379,.T.);
#1393=CARTESIAN_POINT('',(0.,24.4,0.));
#1394=DIRECTION('',(0.,-1.,0.));
#1395=DIRECTION('',(0.,0.,-1.));
#1396=AXIS2_PLACEMENT_3D('',#1393,#1394,#1395);
#1397=CONICAL_SURFACE('',#1396,32.5,0.785398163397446);
#1398=ORIENTED_EDGE('',*,*,#1217,.F.);
#1399=ORIENTED_EDGE('',*,*,#845,.F.);
#1400=ORIENTED_EDGE('',*,*,#1290,.F.);
#1401=CARTESIAN_POINT('',(0.,24.4,0.));
#1402=DIRECTION('',(0.,1.,0.));
#1403=DIRECTION('',(0.,0.,1.));
#1404=AXIS2_PLACEMENT_3D('',#1401,#1402,#1403);
#1405=CIRCLE('',#1404,32.5);
#1406=EDGE_CURVE('E379',#1216,#1273,#1405,.T.);
#1407=ORIENTED_EDGE('',*,*,#1406,.F.);
#1408=EDGE_LOOP('',(#1398,#1399,#1400,#1407));
#1409=FACE_BOUND('',#1408,.T.);
#1410=ADVANCED_FACE('F378',(#1409),#1397,.T.);
#1411=CARTESIAN_POINT('',(0.,24.4,0.));
#1412=DIRECTION('',(0.,-1.,0.));
#1413=DIRECTION('',(0.,0.,-1.));
#1414=AXIS2_PLACEMENT_3D('',#1411,#1412,#1413);
#1415=CONICAL_SURFACE('',#1414,32.5,0.785398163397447);
#1416=ORIENTED_EDGE('',*,*,#1163,.F.);
#1417=ORIENTED_EDGE('',*,*,#110,.F.);
#1418=ORIENTED_EDGE('',*,*,#1200,.F.);
#1419=CARTESIAN_POINT('',(0.,24.4,0.));
#1420=DIRECTION('',(0.,1.,0.));
#1421=DIRECTION('',(0.,0.,1.));
#1422=AXIS2_PLACEMENT_3D('',#1419,#1420,#1421);
#1423=CIRCLE('',#1422,32.5);
#1424=EDGE_CURVE('E391',#1162,#1190,#1423,.T.);
#1425=ORIENTED_EDGE('',*,*,#1424,.F.);
#1426=EDGE_LOOP('',(#1416,#1417,#1418,#1425));
#1427=FACE_BOUND('',#1426,.T.);
#1428=ADVANCED_FACE('F489',(#1427),#1415,.T.);
#1429=CARTESIAN_POINT('',(0.,-14.7,0.));
#1430=DIRECTION('',(0.,-1.,0.));
#1431=DIRECTION('',(0.,0.,-1.));
#1432=AXIS2_PLACEMENT_3D('',#1429,#1430,#1431);
#1433=CONICAL_SURFACE('',#1432,35.,0.785398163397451);
#1434=ORIENTED_EDGE('',*,*,#992,.F.);
#1435=ORIENTED_EDGE('',*,*,#749,.T.);
#1436=ORIENTED_EDGE('',*,*,#932,.F.);
#1437=ORIENTED_EDGE('',*,*,#579,.F.);
#1438=EDGE_LOOP('',(#1434,#1435,#1436,#1437));
#1439=FACE_BOUND('',#1438,.T.);
#1440=ADVANCED_FACE('F539',(#1439),#1433,.T.);
#1441=CARTESIAN_POINT('',(0.,-14.7,0.));
#1442=DIRECTION('',(0.,-1.,0.));
#1443=DIRECTION('',(0.,0.,-1.));
#1444=AXIS2_PLACEMENT_3D('',#1441,#1442,#1443);
#1445=CONICAL_SURFACE('',#1444,35.,0.785398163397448);
#1446=ORIENTED_EDGE('',*,*,#952,.F.);
#1447=ORIENTED_EDGE('',*,*,#730,.T.);
#1448=ORIENTED_EDGE('',*,*,#1072,.F.);
#1449=ORIENTED_EDGE('',*,*,#526,.F.);
#1450=EDGE_LOOP('',(#1446,#1447,#1448,#1449));
#1451=FACE_BOUND('',#1450,.T.);
#1452=ADVANCED_FACE('F543',(#1451),#1445,.T.);
#1453=CARTESIAN_POINT('',(0.,24.4,0.));
#1454=DIRECTION('',(0.,-1.,0.));
#1455=DIRECTION('',(0.,0.,-1.));
#1456=AXIS2_PLACEMENT_3D('',#1453,#1454,#1455);
#1457=CONICAL_SURFACE('',#1456,32.5,0.785398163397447);
#1458=ORIENTED_EDGE('',*,*,#1307,.F.);
#1459=ORIENTED_EDGE('',*,*,#41,.F.);
#1460=ORIENTED_EDGE('',*,*,#1146,.F.);
#1461=CARTESIAN_POINT('',(0.,24.4,0.));
#1462=DIRECTION('',(0.,1.,0.));
#1463=DIRECTION('',(0.,0.,1.));
#1464=AXIS2_PLACEMENT_3D('',#1461,#1462,#1463);
#1465=CIRCLE('',#1464,32.5);
#1466=EDGE_CURVE('E398',#1306,#1136,#1465,.T.);
#1467=ORIENTED_EDGE('',*,*,#1466,.F.);
#1468=EDGE_LOOP('',(#1458,#1459,#1460,#1467));
#1469=FACE_BOUND('',#1468,.T.);
#1470=ADVANCED_FACE('F549',(#1469),#1457,.T.);
#1471=CARTESIAN_POINT('',(0.,24.4,0.));
#1472=DIRECTION('',(0.,1.,0.));
#1473=DIRECTION('',(0.,0.,1.));
#1474=AXIS2_PLACEMENT_3D('',#1471,#1472,#1473);
#1475=PLANE('',#1474);
#1476=CARTESIAN_POINT('',(0.,24.4,0.));
#1477=DIRECTION('',(0.,1.,0.));
#1478=DIRECTION('',(0.,0.,1.));
#1479=AXIS2_PLACEMENT_3D('',#1476,#1477,#1478);
#1480=CIRCLE('',#1479,35.);
#1481=CARTESIAN_POINT('',(0.,24.4,35.));
#1482=VERTEX_POINT('',#1481);
#1483=EDGE_CURVE('E803',#1482,#1482,#1480,.T.);
#1484=ORIENTED_EDGE('',*,*,#1483,.F.);
#1485=EDGE_LOOP('',(#1484));
#1486=FACE_BOUND('',#1485,.T.);
#1487=ORIENTED_EDGE('',*,*,#1274,.F.);
#1488=ORIENTED_EDGE('',*,*,#1388,.T.);
#1489=ORIENTED_EDGE('',*,*,#1328,.F.);
#1490=ORIENTED_EDGE('',*,*,#1466,.T.);
#1491=ORIENTED_EDGE('',*,*,#1182,.F.);
#1492=ORIENTED_EDGE('',*,*,#1424,.T.);
#1493=ORIENTED_EDGE('',*,*,#1236,.F.);
#1494=ORIENTED_EDGE('',*,*,#1406,.T.);
#1495=EDGE_LOOP('',(#1487,#1488,#1489,#1490,#1491,#1492,#1493,#1494));
#1496=FACE_BOUND('',#1495,.T.);
#1497=ADVANCED_FACE('F385',(#1486,#1496),#1475,.F.);
#1498=CARTESIAN_POINT('',(0.,36.6,0.));
#1499=DIRECTION('',(0.,-1.,0.));
#1500=DIRECTION('',(0.,0.,-1.));
#1501=AXIS2_PLACEMENT_3D('',#1498,#1499,#1500);
#1502=CYLINDRICAL_SURFACE('',#1501,35.);
#1503=CARTESIAN_POINT('',(0.,35.6,0.));
#1504=DIRECTION('',(0.,1.,0.));
#1505=DIRECTION('',(0.,0.,1.));
#1506=AXIS2_PLACEMENT_3D('',#1503,#1504,#1505);
#1507=CIRCLE('',#1506,35.);
#1508=CARTESIAN_POINT('',(0.,35.6,35.));
#1509=VERTEX_POINT('',#1508);
#1510=EDGE_CURVE('E657',#1509,#1509,#1507,.F.);
#1511=ORIENTED_EDGE('',*,*,#1510,.T.);
#1512=EDGE_LOOP('',(#1511));
#1513=FACE_BOUND('',#1512,.T.);
#1514=ORIENTED_EDGE('',*,*,#1483,.T.);
#1515=EDGE_LOOP('',(#1514));
#1516=FACE_BOUND('',#1515,.T.);
#1517=ADVANCED_FACE('F425',(#1513,#1516),#1502,.T.);
#1518=CARTESIAN_POINT('',(0.,36.6,0.));
#1519=DIRECTION('',(0.,1.,0.));
#1520=DIRECTION('',(0.,0.,1.));
#1521=AXIS2_PLACEMENT_3D('',#1518,#1519,#1520);
#1522=PLANE('',#1521);
#1523=CARTESIAN_POINT('',(0.,36.6,0.));
#1524=DIRECTION('',(0.,1.,0.));
#1525=DIRECTION('',(0.,0.,1.));
#1526=AXIS2_PLACEMENT_3D('',#1523,#1524,#1525);
#1527=CIRCLE('',#1526,25.);
#1528=CARTESIAN_POINT('',(0.,36.6,25.));
#1529=VERTEX_POINT('',#1528);
#1530=EDGE_CURVE('E1669',#1529,#1529,#1527,.T.);
#1531=ORIENTED_EDGE('',*,*,#1530,.F.);
#1532=EDGE_LOOP('',(#1531));
#1533=FACE_BOUND('',#1532,.T.);
#1534=CARTESIAN_POINT('',(0.,36.6,0.));
#1535=DIRECTION('',(0.,1.,0.));
#1536=DIRECTION('',(0.,0.,1.));
#1537=AXIS2_PLACEMENT_3D('',#1534,#1535,#1536);
#1538=CIRCLE('',#1537,34.);
#1539=CARTESIAN_POINT('',(0.,36.6,34.));
#1540=VERTEX_POINT('',#1539);
#1541=EDGE_CURVE('E647',#1540,#1540,#1538,.T.);
#1542=ORIENTED_EDGE('',*,*,#1541,.T.);
#1543=EDGE_LOOP('',(#1542));
#1544=FACE_BOUND('',#1543,.T.);
#1545=ADVANCED_FACE('F1578',(#1533,#1544),#1522,.T.);
#1546=CARTESIAN_POINT('',(0.,36.6,0.));
#1547=DIRECTION('',(0.,-1.,0.));
#1548=DIRECTION('',(0.,0.,-1.));
#1549=AXIS2_PLACEMENT_3D('',#1546,#1547,#1548);
#1550=CONICAL_SURFACE('',#1549,34.,0.785398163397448);
#1551=ORIENTED_EDGE('',*,*,#1510,.F.);
#1552=EDGE_LOOP('',(#1551));
#1553=FACE_BOUND('',#1552,.T.);
#1554=ORIENTED_EDGE('',*,*,#1541,.F.);
#1555=EDGE_LOOP('',(#1554));
#1556=FACE_BOUND('',#1555,.T.);
#1557=ADVANCED_FACE('F1588',(#1553,#1556),#1550,.T.);
#1558=CARTESIAN_POINT('',(0.,35.6,0.));
#1559=DIRECTION('',(0.,1.,0.));
#1560=DIRECTION('',(0.,0.,1.));
#1561=AXIS2_PLACEMENT_3D('',#1558,#1559,#1560);
#1562=CYLINDRICAL_SURFACE('',#1561,25.);
#1563=CARTESIAN_POINT('',(0.,35.6,0.));
#1564=DIRECTION('',(0.,1.,0.));
#1565=DIRECTION('',(0.,0.,1.));
#1566=AXIS2_PLACEMENT_3D('',#1563,#1564,#1565);
#1567=CIRCLE('',#1566,25.);
#1568=CARTESIAN_POINT('',(0.,35.6,25.));
#1569=VERTEX_POINT('',#1568);
#1570=EDGE_CURVE('E1667',#1569,#1569,#1567,.T.);
#1571=ORIENTED_EDGE('',*,*,#1570,.F.);
#1572=EDGE_LOOP('',(#1571));
#1573=FACE_BOUND('',#1572,.T.);
#1574=ORIENTED_EDGE('',*,*,#1530,.T.);
#1575=EDGE_LOOP('',(#1574));
#1576=FACE_BOUND('',#1575,.T.);
#1577=ADVANCED_FACE('F1597',(#1573,#1576),#1562,.F.);
#1578=CARTESIAN_POINT('',(0.,35.6,0.));
#1579=DIRECTION('',(0.,1.,0.));
#1580=DIRECTION('',(0.,0.,1.));
#1581=AXIS2_PLACEMENT_3D('',#1578,#1579,#1580);
#1582=PLANE('',#1581);
#1583=CARTESIAN_POINT('',(0.,35.6,0.));
#1584=DIRECTION('',(0.,1.,0.));
#1585=DIRECTION('',(0.,0.,1.));
#1586=AXIS2_PLACEMENT_3D('',#1583,#1584,#1585);
#1587=CIRCLE('',#1586,21.);
#1588=CARTESIAN_POINT('',(0.,35.6,21.));
#1589=VERTEX_POINT('',#1588);
#1590=EDGE_CURVE('E11',#1589,#1589,#1587,.F.);
#1591=ORIENTED_EDGE('',*,*,#1590,.T.);
#1592=EDGE_LOOP('',(#1591));
#1593=FACE_BOUND('',#1592,.T.);
#1594=ORIENTED_EDGE('',*,*,#1570,.T.);
#1595=EDGE_LOOP('',(#1594));
#1596=FACE_BOUND('',#1595,.T.);
#1597=ADVANCED_FACE('F1605',(#1593,#1596),#1582,.T.);
#1598=CARTESIAN_POINT('',(0.,-79.5543289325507,0.));
#1599=DIRECTION('',(0.,1.,0.));
#1600=DIRECTION('',(0.,0.,1.));
#1601=AXIS2_PLACEMENT_3D('',#1598,#1599,#1600);
#1602=CYLINDRICAL_SURFACE('',#1601,19.5);
#1603=CARTESIAN_POINT('',(0.,-22.9,0.));
#1604=DIRECTION('',(0.,-1.,0.));
#1605=DIRECTION('',(0.,0.,-1.));
#1606=AXIS2_PLACEMENT_3D('',#1603,#1604,#1605);
#1607=CIRCLE('',#1606,19.5);
#1608=CARTESIAN_POINT('',(0.,-22.9,-19.5));
#1609=VERTEX_POINT('',#1608);
#1610=EDGE_CURVE('E48',#1609,#1609,#1607,.T.);
#1611=ORIENTED_EDGE('',*,*,#1610,.T.);
#1612=EDGE_LOOP('',(#1611));
#1613=FACE_BOUND('',#1612,.T.);
#1614=CARTESIAN_POINT('',(0.,34.1,0.));
#1615=DIRECTION('',(0.,1.,0.));
#1616=DIRECTION('',(0.,0.,1.));
#1617=AXIS2_PLACEMENT_3D('',#1614,#1615,#1616);
#1618=CIRCLE('',#1617,19.5);
#1619=CARTESIAN_POINT('',(0.,34.1,19.5));
#1620=VERTEX_POINT('',#1619);
#1621=EDGE_CURVE('E665',#1620,#1620,#1618,.T.);
#1622=ORIENTED_EDGE('',*,*,#1621,.T.);
#1623=EDGE_LOOP('',(#1622));
#1624=FACE_BOUND('',#1623,.T.);
#1625=ADVANCED_FACE('F673',(#1613,#1624),#1602,.F.);
#1626=CARTESIAN_POINT('',(0.,-24.4,0.));
#1627=DIRECTION('',(0.,-1.,0.));
#1628=DIRECTION('',(0.,0.,-1.));
#1629=AXIS2_PLACEMENT_3D('',#1626,#1627,#1628);
#1630=CONICAL_SURFACE('',#1629,21.,0.785398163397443);
#1631=ORIENTED_EDGE('',*,*,#1610,.F.);
#1632=EDGE_LOOP('',(#1631));
#1633=FACE_BOUND('',#1632,.T.);
#1634=ORIENTED_EDGE('',*,*,#602,.F.);
#1635=EDGE_LOOP('',(#1634));
#1636=FACE_BOUND('',#1635,.T.);
#1637=ADVANCED_FACE('F676',(#1633,#1636),#1630,.F.);
#1638=CARTESIAN_POINT('',(0.,34.1,0.));
#1639=DIRECTION('',(0.,1.,0.));
#1640=DIRECTION('',(0.,0.,1.));
#1641=AXIS2_PLACEMENT_3D('',#1638,#1639,#1640);
#1642=CONICAL_SURFACE('',#1641,19.5,0.78539816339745);
#1643=CARTESIAN_POINT('',(0.,35.6,21.));
#1644=CARTESIAN_POINT('',(0.,35.584375,20.984375));
#1645=CARTESIAN_POINT('',(0.,35.56875,20.96875));
#1646=CARTESIAN_POINT('',(0.,35.5375,20.9375));
#1647=CARTESIAN_POINT('',(0.,35.521875,20.921875));
#1648=CARTESIAN_POINT('',(0.,35.490625,20.890625));
#1649=CARTESIAN_POINT('',(0.,35.475,20.875));
#1650=CARTESIAN_POINT('',(0.,35.44375,20.84375));
#1651=CARTESIAN_POINT('',(0.,35.428125,20.828125));
#1652=CARTESIAN_POINT('',(0.,35.396875,20.796875));
#1653=CARTESIAN_POINT('',(0.,35.38125,20.78125));
#1654=CARTESIAN_POINT('',(0.,35.35,20.75));
#1655=CARTESIAN_POINT('',(0.,35.334375,20.734375));
#1656=CARTESIAN_POINT('',(0.,35.303125,20.703125));
#1657=CARTESIAN_POINT('',(0.,35.2875,20.6875));
#1658=CARTESIAN_POINT('',(0.,35.25625,20.65625));
#1659=CARTESIAN_POINT('',(0.,35.240625,20.640625));
#1660=CARTESIAN_POINT('',(0.,35.209375,20.609375));
#1661=CARTESIAN_POINT('',(0.,35.19375,20.59375));
#1662=CARTESIAN_POINT('',(0.,35.1625,20.5625));
#1663=CARTESIAN_POINT('',(0.,35.146875,20.546875));
#1664=CARTESIAN_POINT('',(0.,35.115625,20.515625));
#1665=CARTESIAN_POINT('',(0.,35.1,20.5));
#1666=CARTESIAN_POINT('',(0.,35.06875,20.46875));
#1667=CARTESIAN_POINT('',(0.,35.053125,20.453125));
#1668=CARTESIAN_POINT('',(0.,35.021875,20.421875));
#1669=CARTESIAN_POINT('',(0.,35.00625,20.40625));
#1670=CARTESIAN_POINT('',(0.,34.975,20.375));
#1671=CARTESIAN_POINT('',(0.,34.959375,20.359375));
#1672=CARTESIAN_POINT('',(0.,34.928125,20.328125));
#1673=CARTESIAN_POINT('',(0.,34.9125,20.3125));
#1674=CARTESIAN_POINT('',(0.,34.88125,20.28125));
#1675=CARTESIAN_POINT('',(0.,34.865625,20.265625));
#1676=CARTESIAN_POINT('',(0.,34.834375,20.234375));
#1677=CARTESIAN_POINT('',(0.,34.81875,20.21875));
#1678=CARTESIAN_POINT('',(0.,34.7875,20.1875));
#1679=CARTESIAN_POINT('',(0.,34.771875,20.171875));
#1680=CARTESIAN_POINT('',(0.,34.740625,20.140625));
#1681=CARTESIAN_POINT('',(0.,34.725,20.125));
#1682=CARTESIAN_POINT('',(0.,34.69375,20.09375));
#1683=CARTESIAN_POINT('',(0.,34.678125,20.078125));
#1684=CARTESIAN_POINT('',(0.,34.646875,20.046875));
#1685=CARTESIAN_POINT('',(0.,34.63125,20.03125));
#1686=CARTESIAN_POINT('',(0.,34.6,20.));
#1687=CARTESIAN_POINT('',(0.,34.584375,19.984375));
#1688=CARTESIAN_POINT('',(0.,34.553125,19.953125));
#1689=CARTESIAN_POINT('',(0.,34.5375,19.9375));
#1690=CARTESIAN_POINT('',(0.,34.50625,19.90625));
#1691=CARTESIAN_POINT('',(0.,34.490625,19.890625));
#1692=CARTESIAN_POINT('',(0.,34.459375,19.859375));
#1693=CARTESIAN_POINT('',(0.,34.44375,19.84375));
#1694=CARTESIAN_POINT('',(0.,34.4125,19.8125));
#1695=CARTESIAN_POINT('',(0.,34.396875,19.796875));
#1696=CARTESIAN_POINT('',(0.,34.365625,19.765625));
#1697=CARTESIAN_POINT('',(0.,34.35,19.75));
#1698=CARTESIAN_POINT('',(0.,34.31875,19.71875));
#1699=CARTESIAN_POINT('',(0.,34.303125,19.703125));
#1700=CARTESIAN_POINT('',(0.,34.271875,19.671875));
#1701=CARTESIAN_POINT('',(0.,34.25625,19.65625));
#1702=CARTESIAN_POINT('',(0.,34.225,19.625));
#1703=CARTESIAN_POINT('',(0.,34.209375,19.609375));
#1704=CARTESIAN_POINT('',(0.,34.178125,19.578125));
#1705=CARTESIAN_POINT('',(0.,34.1625,19.5625));
#1706=CARTESIAN_POINT('',(0.,34.13125,19.53125));
#1707=CARTESIAN_POINT('',(0.,34.115625,19.515625));
#1708=CARTESIAN_POINT('',(0.,34.1,19.5));
#1709=B_SPLINE_CURVE_WITH_KNOTS('',3,(#1643,#1644,#1645,#1646,#1647,#1648,#1649,#1650,#1651,
#1652,#1653,#1654,#1655,#1656,#1657,#1658,#1659,#1660,#1661,#1662,#1663,#1664,#1665,#1666,#1667,
#1668,#1669,#1670,#1671,#1672,#1673,#1674,#1675,#1676,#1677,#1678,#1679,#1680,#1681,#1682,#1683,
#1684,#1685,#1686,#1687,#1688,#1689,#1690,#1691,#1692,#1693,#1694,#1695,#1696,#1697,#1698,#1699,
#1700,#1701,#1702,#1703,#1704,#1705,#1706,#1707,#1708),.UNSPECIFIED.,.F.,.F.,(4,2,2,2,2,2,2,2,2,
2,2,2,2,2,2,2,2,2,2,2,2,2,2,2,2,2,2,2,2,2,2,2,4),(0.,0.066291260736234,0.132582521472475,
0.198873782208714,0.265165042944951,0.33145630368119,0.397747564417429,0.464038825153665,
0.530330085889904,0.596621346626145,0.662912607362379,0.729203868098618,0.79549512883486,
0.861786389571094,0.928077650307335,0.994368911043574,1.06066017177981,1.12695143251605,
1.19324269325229,1.25953395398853,1.32582521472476,1.392116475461,1.45840773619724,
1.52469899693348,1.59099025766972,1.65728151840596,1.72357277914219,1.78986403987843,
1.85615530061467,1.92244656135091,1.98873782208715,2.05502908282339,2.12132034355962),.UNSPECIFIED.);
#1710=EDGE_CURVE('BSEAM41',#1589,#1620,#1709,.T.);
#1711=ORIENTED_EDGE('',*,*,#1590,.F.);
#1712=ORIENTED_EDGE('',*,*,#1621,.F.);
#1713=ORIENTED_EDGE('',*,*,#1710,.T.);
#1714=ORIENTED_EDGE('',*,*,#1710,.F.);
#1715=EDGE_LOOP('',(#1711,#1713,#1712,#1714));
#1716=FACE_BOUND('',#1715,.T.);
#1717=ADVANCED_FACE('F41',(#1716),#1642,.F.);
#1718=CLOSED_SHELL('',(#60,#92,#124,#244,#384,#426,#453,#480,#489,#498,#507,#541,#565,#589,#709,
#829,#856,#868,#890,#899,#918,#938,#958,#978,#998,#1018,#1038,#1058,#1078,#1085,#1092,#1099,
#1106,#1113,#1120,#1127,#1134,#1152,#1170,#1188,#1206,#1224,#1242,#1260,#1281,#1296,#1314,#1335,
#1350,#1362,#1374,#1392,#1410,#1428,#1440,#1452,#1470,#1497,#1517,#1545,#1557,#1577,#1597,#1625,
#1637,#1717));
#1719=MANIFOLD_SOLID_BREP('B2',#1718);
#1720=ADVANCED_BREP_SHAPE_REPRESENTATION('',(#18,#1719),#14);
#1721=SHAPE_DEFINITION_REPRESENTATION(#9,#1720);
ENDSEC;
END-ISO-10303-21;
